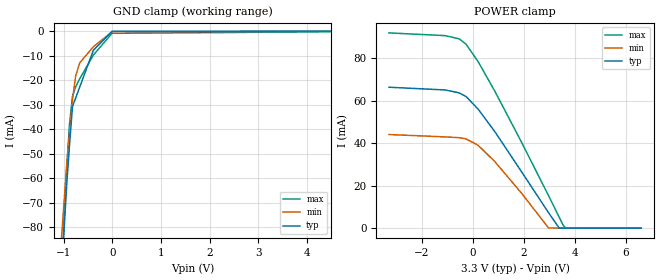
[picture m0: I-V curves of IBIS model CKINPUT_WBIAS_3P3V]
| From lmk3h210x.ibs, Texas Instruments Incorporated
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[Model]   CKINPUT_WBIAS_3P3V
Model_type   Input
Vinl = 0.2
Vinh = 0.4
|   typ   min   max
C_comp   1.5pF   1.4pF   1.6pF
[Voltage Range]   3.3   2.97   3.597
[Temperature Range]   50   125   -40
[Power Clamp Reference]   3.3   2.97   3.597
[GND Clamp Reference]   0   0   0
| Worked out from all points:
|   GND clamp passes 1 mA (typ) near -0.05 V on its own axis
[GND Clamp]
|   Voltage   I(typ)   I(min)   I(max)
-3.3V     -1.023A    -928mA     -1.13A
-1.209V   -162mA     -139.3mA   -169mA
-1.065V   -107.8mA   -91.57mA   -107.2mA
-1.051V   -102.5mA   -86.96mA   -101.7mA
-934.8mV  -62.44mA   -54.38mA   -56.05mA
-877.3mV  -46.53mA   -41.62mA   -37.87mA
-816.2mV  -30.81mA   -28.06mA   -26.49mA
-751.2mV  -27.32mA   -18.29mA   -22.73mA
-668.2mV  -22.87mA   -12.99mA   -19.46mA
-388.1mV  -7.841mA   -6.381mA   -9.788mA
-3.764mV  -73.56uA   -283.4uA   -906.7uA
6.6V      0A         0A         0A
[POWER Clamp]
|   Voltage   I(typ)   I(min)   I(max)
-3.3V     66.27mA    44.03mA    91.82mA
-1.091V   64.99mA    42.91mA    90.53mA
-541.9mV  63.61mA    42.54mA    89.01mA
-271.8mV  61.9mA     41.99mA    86.51mA
207.3mV   55.89mA    38.9mA     78.19mA
858.4mV   45.36mA    31.27mA    64.37mA
1.912V    26.42mA    16.34mA    40.26mA
2.964V    7.29mA     100.4uA    15.3mA
3.386V    0A         0A         5.1mA
3.55V     0A         0A         1.152mA
3.653V    0A         0A         0A
6.6V      0A         0A         0A
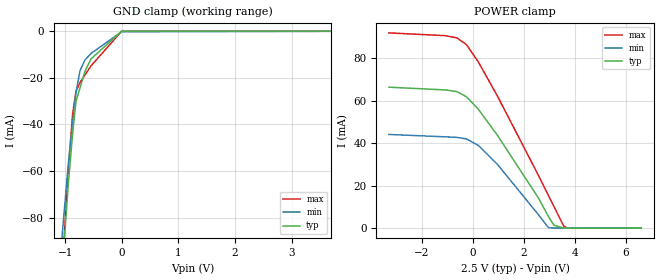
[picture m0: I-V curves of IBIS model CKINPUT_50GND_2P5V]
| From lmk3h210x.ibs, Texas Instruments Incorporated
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[Model]   CKINPUT_50GND_2P5V
Model_type   Input
Vinl = 0.2
Vinh = 0.4
|   typ   min   max
C_comp   1.5pF   1.4pF   1.6pF
[Voltage Range]   2.5   2.25   2.75
[Temperature Range]   50   125   -40
[Power Clamp Reference]   2.5   2.25   2.75
[GND Clamp Reference]   0   0   0
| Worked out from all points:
|   GND clamp passes 1 mA (typ) near -0.05 V on its own axis
[GND Clamp]
|   Voltage   I(typ)   I(min)   I(max)
-3.3V     -1.023A    -928mA     -1.13A
-1.151V   -140.2mA   -118.9mA   -144.2mA
-1.074V   -110.9mA   -94.04mA   -110.7mA
-1.051V   -102.5mA   -86.96mA   -101.9mA
-944.7mV  -65.64mA   -57.1mA    -59.44mA
-868.9mV  -44.36mA   -39.76mA   -35.72mA
-808.8mV  -30.19mA   -26.54mA   -25.79mA
-738.2mV  -24.45mA   -17.01mA   -22.12mA
-649.7mV  -17.24mA   -12.37mA   -18.78mA
-541.2mV  -11.89mA   -9.581mA   -14.87mA
-3.764mV  -73.56uA   -283.4uA   -91.89uA
6.6V      0A         0A         0A
[POWER Clamp]
-3.3V     66.27mA    44.03mA    91.82mA
-1.074V   64.97mA    42.9mA     90.51mA
-636.3mV  64.21mA    42.66mA    89.48mA
-258.6mV  61.78mA    41.95mA    86.34mA
207.3mV   55.92mA    38.9mA     78.18mA
957.4mV   43.66mA    29.96mA    62.14mA
2.566V    14.15mA    6.307mA    24.82mA
2.964V    5.373mA    100.4uA    15.27mA
3.174V    1.35mA     0A         10.21mA
3.561V    -19.07uA   0A         884.6uA
3.708V    -68.5uA    0A         0A
6.6V      0A         0A         0A
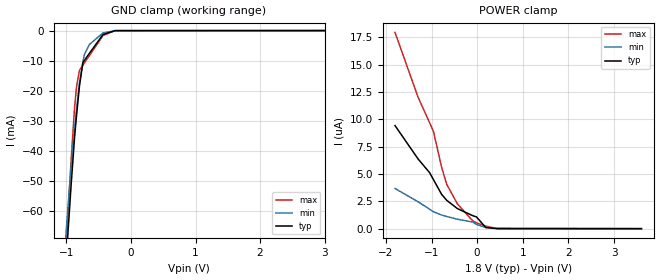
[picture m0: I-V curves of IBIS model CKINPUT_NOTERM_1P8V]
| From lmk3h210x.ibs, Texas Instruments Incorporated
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[Model]   CKINPUT_NOTERM_1P8V
Model_type   Input
Vinl = 0.2
Vinh = 0.4
|   typ   min   max
C_comp   1.5pF   1.4pF   1.6pF
[Voltage Range]   1.8   1.71   1.89
[Temperature Range]   50   125   -40
[Power Clamp Reference]   1.8   1.71   1.89
[GND Clamp Reference]   0   0   0
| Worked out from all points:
|   GND clamp passes 1 mA (typ) near -0.41 V on its own axis
[GND Clamp]
|   Voltage   I(typ)   I(min)   I(max)
-1.8V     -389.6mA   -347.8mA   -423.4mA
-1.005V   -76.24mA   -66.85mA   -71.29mA
-926.6mV  -51.02mA   -44.76mA   -42.66mA
-873.8mV  -35.39mA   -32.34mA   -25.47mA
-841.9mV  -27.83mA   -25.8mA    -18.39mA
-797.7mV  -18.31mA   -17.26mA   -13.14mA
-744.9mV  -10.64mA   -10.39mA   -11.48mA
-720.6mV  -9.896mA   -7.908mA   -10.71mA
-643.7mV  -7.534mA   -4.603mA   -8.278mA
-433.6mV  -1.316mA   -796.2uA   -1.64mA
-246.2mV  -24.72uA   -20.8uA    -13.5uA
3.6V      0A         0A         0A
[POWER Clamp]
|   Voltage   I(typ)   I(min)   I(max)
-1.8V     9.428uA    3.675uA    17.95uA
-1.295V   6.381uA    2.46uA     12.03uA
-1.04V    5.109uA    1.775uA    9.674uA
-957.7mV  4.488uA    1.548uA    8.894uA
-777.2mV  3.128uA    1.244uA    5.598uA
-666.5mV  2.591uA    1.111uA    4.053uA
-432.7mV  1.834uA    861.5nA    2.263uA
-96.2mV   1.188uA    605nA      706nA
-13.98mV  1.073uA    384.4nA    528.4nA
187.6mV   105.9nA    109.1nA    233.9nA
443.4mV   0A         32.14nA    0A
3.6V      0A         0A         0A
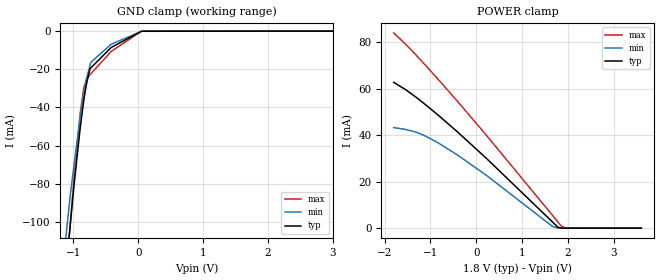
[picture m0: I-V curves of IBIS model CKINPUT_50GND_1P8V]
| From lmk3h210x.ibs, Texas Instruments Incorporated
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[Model]   CKINPUT_50GND_1P8V
Model_type   Input
Vinl = 0.2
Vinh = 0.4
|   typ   min   max
C_comp   1.5pF   1.4pF   1.6pF
[Voltage Range]   1.8   1.71   1.89
[Temperature Range]   50   125   -40
[Power Clamp Reference]   1.8   1.71   1.89
[GND Clamp Reference]   0   0   0
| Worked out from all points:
|   GND clamp passes 1 mA (typ) near -0.05 V on its own axis
[GND Clamp]
|   Voltage   I(typ)   I(min)   I(max)
-1.8V     -399.1mA   -354.1mA   -436.1mA
-1.137V   -133.8mA   -114.7mA   -137.8mA
-1.05V    -101.9mA   -86.43mA   -101.5mA
-988.7mV  -80.14mA   -69.6mA    -76.04mA
-894.5mV  -50.39mA   -44.5mA    -42.71mA
-839.7mV  -36.15mA   -32.93mA   -29.62mA
-799.7mV  -27.85mA   -24.95mA   -25.26mA
-743.5mV  -19.7mA    -17.99mA   -22.83mA
-729.7mV  -19.23mA   -16.29mA   -22.32mA
-418.2mV  -8.588mA   -6.921mA   -10.69mA
50.38mV   -92.85uA   -74.37uA   0A
3.6V      0A         0A         0A
[POWER Clamp]
|   Voltage   I(typ)   I(min)   I(max)
-1.8V     62.67mA    43.23mA    83.91mA
-1.539V   59.51mA    42.41mA    79.02mA
-1.318V   56.36mA    41.32mA    74.52mA
-1.111V   53.13mA    39.63mA    70.1mA
-835.3mV  48.67mA    36.72mA    64.09mA
-418.2mV  41.53mA    31.56mA    54.72mA
231.4mV   29.81mA    22.56mA    39.68mA
1.664V    2.633mA    722uA      5.471mA
1.777V    444.1uA    0A         2.738mA
1.858V    0A         0A         770uA
1.958V    0A         0A         0A
3.6V      0A         0A         0A
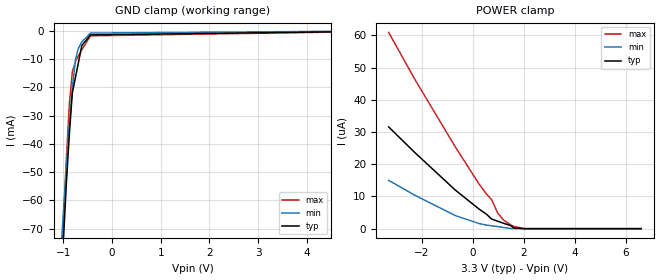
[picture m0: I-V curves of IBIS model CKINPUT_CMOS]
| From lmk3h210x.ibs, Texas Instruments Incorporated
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[Model]   CKINPUT_CMOS
Model_type   Input
Vinl = 0.5
Vinh = 1.2
|   typ   min   max
C_comp   1.5pF   1.4pF   1.6pF
[Voltage Range]   3.3   2.97   3.597
[Temperature Range]   50   125   -40
[Power Clamp Reference]   3.3   2.97   3.597
[GND Clamp Reference]   0   0   0
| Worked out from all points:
|   GND clamp passes 1 mA (typ) near -0.41 V on its own axis
[GND Clamp]
|   Voltage   I(typ)   I(min)   I(max)
-3.3V     -1.015A    -923.7mA   -1.116A
-1.08V    -103.9mA   -88.87mA   -101.9mA
-1.05V    -92.77mA   -79.14mA   -89.89mA
-1.021V   -82.14mA   -70.55mA   -78.34mA
-937.6mV  -54.32mA   -47.76mA   -45.53mA
-874.8mV  -36.37mA   -33.4mA    -25.73mA
-813.6mV  -21.97mA   -19.98mA   -14.47mA
-749.1mV  -16.43mA   -10.38mA   -10.86mA
-697mV    -11.95mA   -6.522mA   -9.166mA
-619.3mV  -5.276mA   -3.993mA   -6.738mA
-441mV    -1.521mA   -879.1uA   -1.855mA
6.6V      0A         0A         0A
[POWER Clamp]
|   Voltage   I(typ)   I(min)   I(max)
-3.3V     31.59uA    15uA       60.94uA
-2.284V   23.71uA    10.43uA    46.51uA
-697mV    12.05uA    4.095uA    25.51uA
248.9mV   6.057uA    1.574uA    13.82uA
540.5mV   4.458uA    1.101uA    10.73uA
737.3mV   2.976uA    894nA      8.989uA
979.7mV   2.301uA    639.5nA    4.797uA
1.214V    1.648uA    347.3nA    2.6uA
1.496V    924.3nA    80.75nA    1.143uA
1.614V    177.9nA    48.28nA    697.8nA
2.025V    0A         0A         1.319nA
6.6V      0A         0A         0A
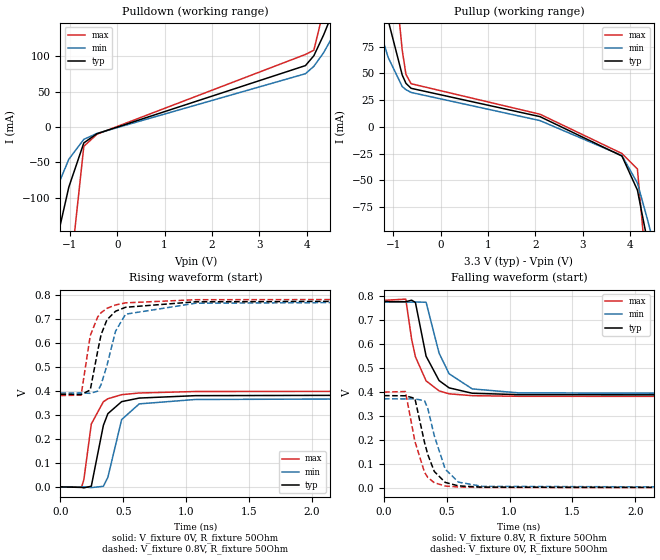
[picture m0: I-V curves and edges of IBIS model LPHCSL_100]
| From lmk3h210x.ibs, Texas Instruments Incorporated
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[Model]   LPHCSL_100
Model_type   Output
Polarity   Non-Inverting
Vmeas = 0.375
Vref = 0
Cref = 2pF
Rref = 100000
|   typ   min   max
C_comp   2.5pF   2pF   3pF
[Voltage Range]   3.3   3.135   3.465
[Temperature Range]   45   125   -40
[Pullup Reference]   3.3   3.135   3.465
[Pulldown Reference]   -0   0   -0
[Power Clamp Reference]   3.3   3.135   3.465
[GND Clamp Reference]   0   0   0
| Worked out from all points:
|   slope of the pulldown table from 0 to 0.495 V, typ, clamps not added: 46.9 ohm
|   slope of the pullup table from 0 to 0.495 V, typ, clamps not added: 121 ohm
|   falling waveform, V_fixture 0.8V, R_fixture 50Ohm: 20-80 % time 134ps typ, 152ps min, 118ps max; typ from 0.778 V to 0.387 V
|   rising waveform, V_fixture 0V, R_fixture 50Ohm: 20-80 % time 98ps typ, 113ps min, 87.4ps max; typ from 0 V to 0.385 V
|   rising waveform, V_fixture 0.8V, R_fixture 50Ohm: 20-80 % time 109ps typ, 133ps min, 96ps max; typ from 0.387 V to 0.778 V
|   falling waveform, V_fixture 0V, R_fixture 50Ohm: 20-80 % time 119ps typ, 126ps min, 110ps max; typ from 0.385 V to 0 V
[Pulldown]
|   Voltage   I(typ)   I(min)   I(max)
-3.3V     -899.1mA   -528.2mA   -2.692A
-1.944V   -395.2mA   -213.5mA   -1.201A
-1.241V   -149.6mA   -80.86mA   -439.1mA
-1.023V   -85.09mA   -45.71mA   -224.9mA
-706.2mV  -22.59mA   -17.56mA   -27.46mA
-429mV    -9.629mA   -9.193mA   -10.32mA
3.977V    86.76mA    75.29mA    102.5mA
4.155V    100.7mA    85.73mA    108.6mA
4.363V    130.4mA    105.2mA    165.8mA
4.59V     167.8mA    132.6mA    261.3mA
4.907V    230.9mA    176.3mA    408.7mA
6.6V      624.2mA    482.1mA    1.302A
[Pullup]
|   Voltage   I(typ)   I(min)   I(max)
-3.3V     597.5mA    427.6mA    1.347A
-1.617V   206.2mA    137.9mA    457.2mA
-1.112V   99.56mA    64.93mA    204.4mA
-815.1mV  48.52mA    37.71mA    71.73mA
-735.9mV  40.7mA     34.8mA     49.01mA
-627mV    36.08mA    32.22mA    40.36mA
2.095V    9.633mA    5.938mA    11.89mA
3.828V    -27.21mA   -26.75mA   -24.82mA
4.155V    -59.05mA   -52.46mA   -39.3mA
4.372V    -108mA     -87.23mA   -147.2mA
4.491V    -142.5mA   -107.7mA   -240.8mA
6.6V      -930.7mA   -594.1mA   -2.541A
[Ramp]
R_load = 50
|   typ   min   max
dV/dt_r   0.230932/9.7996e-11   0.222863/1.12745e-10   0.239773/8.73447e-11
dV/dt_f   0.234814/1.33534e-10   0.230538/1.51007e-10   0.241163/1.17227e-10
[Falling Waveform]
V_fixture = 0.8V
V_fixture_min = 0.8V
V_fixture_max = 0.8V
R_fixture = 50Ohm
C_fixture = 0F
|   Time   V(typ)   V(min)   V(max)
0s        777.9mV    775.9mV    783.1mV
173.3ps   777.2mV    775.5mV    788mV
220.1ps   783.6mV    775.4mV    620.1mV
250.2ps   773.8mV    776.2mV    547.1mV
335.1ps   549.9mV    774.8mV    446.8mV
438.6ps   448mV      562.4mV    405mV
518.4ps   417.6mV    476.5mV    392.7mV
702.4ps   395.1mV    413.2mV    384.9mV
1.074ns   389.2mV    396.6mV    382.4mV
5ns       386.6mV    391.7mV    381.2mV
[Rising Waveform]
V_fixture = 0V
V_fixture_min = 0V
V_fixture_max = 0V
R_fixture = 50Ohm
C_fixture = 0F
|   Time   V(typ)   V(min)   V(max)
0s        187uV      283.4uV    113.6uV
167.8ps   -1.962mV   152.4uV    -1.11mV
186.3ps   -3.82mV    138uV      30.16mV
245.8ps   3.068mV    -2.748mV   262.6mV
341.6ps   256.3mV    2.698mV    355.1mV
377.6ps   305.6mV    40.1mV     367.7mV
487.3ps   355.7mV    280.9mV    384.7mV
627.4ps   370.6mV    346.4mV    391.7mV
1.074ns   380.6mV    364.6mV    397.9mV
5ns       385.1mV    371.7mV    399.7mV
[Rising Waveform]
V_fixture = 0.8V
V_fixture_min = 0.8V
V_fixture_max = 0.8V
R_fixture = 50Ohm
C_fixture = 0F
|   Time   V(typ)   V(min)   V(max)
0s        386.6mV    391.7mV    381.2mV
164.7ps   385.2mV    391.9mV    382.7mV
237.3ps   404.2mV    390.3mV    631.1mV
296.4ps   565.9mV    399.4mV    708.7mV
323.7ps   635.2mV    426.7mV    726.5mV
370.6ps   697.3mV    507.6mV    744.7mV
438.6ps   732.6mV    649.3mV    758.7mV
518.4ps   749.1mV    720.2mV    767.6mV
1.074ns   771.9mV    765.9mV    780.6mV
5ns       777.9mV    775.8mV    783.1mV
[Falling Waveform]
|Gnd
V_fixture = 0V
V_fixture_min = 0V
V_fixture_max = 0V
R_fixture = 50Ohm
C_fixture = 0F
|   Time   V(typ)   V(min)   V(max)
0s        385.1mV    371.8mV    399.8mV
170.6ps   384.5mV    371.5mV    402.3mV
245.8ps   373.7mV    371.8mV    194.7mV
322.9ps   189mV      363.7mV    64.61mV
349.3ps   138.1mV    330.6mV    43.25mV
400.4ps   68.64mV    217.6mV    21.6mV
487.3ps   22.89mV    78.43mV    7.784mV
592ps     8.424mV    24.03mV    3.782mV
783.6ps   3.06mV     6.308mV    1.849mV
5ns       186.4uV    283.2uV    112.6uV
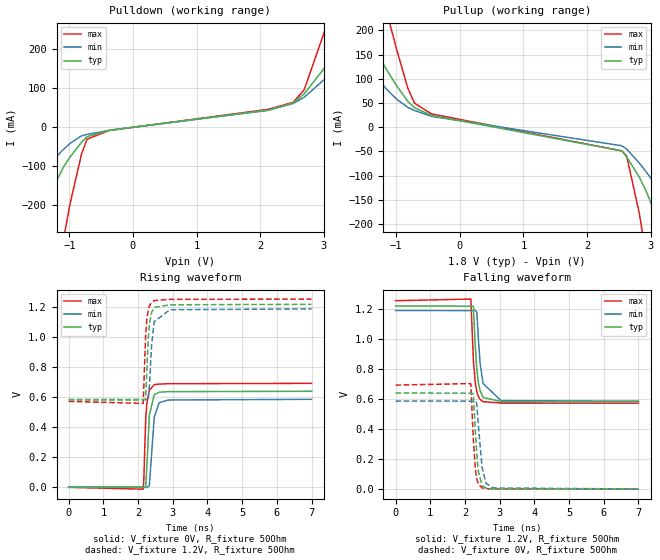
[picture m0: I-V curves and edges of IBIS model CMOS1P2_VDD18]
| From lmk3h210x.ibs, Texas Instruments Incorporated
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[Model]   CMOS1P2_VDD18
Model_type   Output
Polarity   Non-Inverting
Vmeas = 0.9
Vref = 0.9
Cref = 2pF
Rref = 100000
|   typ   min   max
C_comp   2.5pF   2pF   3pF
[Voltage Range]   1.8   1.71   1.89
[Temperature Range]   45   125   -40
[Pullup Reference]   1.8   1.71   1.89
[Pulldown Reference]   0   -0   -0
[Power Clamp Reference]   1.8   1.71   1.89
[GND Clamp Reference]   0   0   0
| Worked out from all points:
|   slope of the pulldown table from 0 to 0.27 V, typ, clamps not added: 46.7 ohm
|   slope of the pullup table from 0 to 0.27 V, typ, clamps not added: 45.5 ohm
|   falling waveform, V_fixture 1.2V, R_fixture 50Ohm: 20-80 % time 115ps typ, 147ps min, 100ps max; typ from 1.22 V to 0.581 V
|   rising waveform, V_fixture 0V, R_fixture 50Ohm: 20-80 % time 87.9ps typ, 107ps min, 76.4ps max; typ from 0 V to 0.639 V
|   rising waveform, V_fixture 1.2V, R_fixture 50Ohm: 20-80 % time 85.2ps typ, 105ps min, 77.4ps max; typ from 0.581 V to 1.22 V
|   falling waveform, V_fixture 0V, R_fixture 50Ohm: 20-80 % time 108ps typ, 138ps min, 98.5ps max; typ from 0.639 V to 0 V
[Pulldown]
|   Voltage   I(typ)   I(min)   I(max)
-1.8V     -348.1mA   -190.5mA   -1.047A
-1.411V   -207.4mA   -111.6mA   -626.1mA
-1.093V   -103.4mA   -57.49mA   -291.6mA
-990mV    -77.57mA   -42.23mA   -199mA
-806.4mV  -38.77mA   -22.26mA   -68.97mA
-720mV    -24.68mA   -18.72mA   -31.09mA
-369mV    -8.092mA   -8.074mA   -8.438mA
2.126V    43.84mA    43.24mA    45.83mA
2.52V     62.07mA    60.84mA    63.89mA
2.693V    85.76mA    77.08mA    96.32mA
3.109V    172.6mA    137mA      291.8mA
3.6V      287mA      218.8mA    549.2mA
[Pullup]
|   Voltage   I(typ)   I(min)   I(max)
-1.8V     265.9mA    179.6mA    578.2mA
-1.152V   119.2mA    78.6mA     240.4mA
-990mV    85.03mA    57.39mA    159.7mA
-817.2mV  53.27mA    40.88mA    80.81mA
-709.2mV  40.09mA    34.26mA    49.33mA
-444.6mV  24.23mA    22.25mA    27.37mA
2.547V    -48.97mA   -38.41mA   -49.02mA
2.623V    -61.46mA   -45.25mA   -59.45mA
2.822V    -103mA     -74.18mA   -177.9mA
2.93V     -132.1mA   -92.28mA   -265.7mA
3.13V     -197.9mA   -128.1mA   -463.8mA
3.6V      -370.6mA   -226.7mA   -978.4mA
[Ramp]
R_load = 50
|   typ   min   max
dV/dt_r   0.383123/8.79707e-11   0.350417/1.07146e-10   0.414781/7.6285e-11
dV/dt_f   0.381702/1.14879e-10   0.361584/1.46587e-10   0.408396/1.00091e-10
[Falling Waveform]
V_fixture = 1.2V
V_fixture_min = 1.2V
V_fixture_max = 1.2V
R_fixture = 50Ohm
C_fixture = 0F
|   Time   V(typ)   V(min)   V(max)
0s        1.217V     1.187V     1.252V
2.17ns    1.216V     1.186V     1.263V
2.243ns   1.216V     1.186V     856.5mV
2.295ns   960.4mV    1.19V      711.7mV
2.341ns   796.5mV    1.176V     649mV
2.382ns   713.6mV    1.018V     618.3mV
2.436ns   655.1mV    837.6mV    596.7mV
2.52ns    610.1mV    702.7mV    581.3mV
3.04ns    582mV      588.3mV    572.2mV
7ns       580.9mV    584.1mV    571.4mV
[Rising Waveform]
V_fixture = 0V
V_fixture_min = 0V
V_fixture_max = 0V
R_fixture = 50Ohm
C_fixture = 0F
|   Time   V(typ)   V(min)   V(max)
0s        303uV      1.493mV    224.7uV
2.147ns   351.5uV    1.434mV    -12.05mV
2.163ns   -1.108mV   1.434mV    36.21mV
2.22ns    -487.3uV   535.5uV    456.3mV
2.252ns   137.3mV    -2.299mV   556.2mV
2.325ns   481mV      11.27mV    645.6mV
2.465ns   616.1mV    467.2mV    683.1mV
2.608ns   632.5mV    563mV      686.3mV
2.865ns   636.4mV    580.8mV    689.4mV
7ns       638.8mV    585.5mV    691.5mV
[Rising Waveform]
V_fixture = 1.2V
V_fixture_min = 1.2V
V_fixture_max = 1.2V
R_fixture = 50Ohm
C_fixture = 0F
|   Time   V(typ)   V(min)   V(max)
0s        581.1mV    584.4mV    571.5mV
2.147ns   581.2mV    584.4mV    558.2mV
2.216ns   584mV      583.8mV    1.003V
2.252ns   775.6mV    581.3mV    1.117V
2.289ns   976.9mV    584.6mV    1.175V
2.33ns    1.094V     687.7mV    1.208V
2.392ns   1.165V     952.8mV    1.23V
2.465ns   1.196V     1.102V     1.242V
2.915ns   1.214V     1.181V     1.25V
7ns       1.217V     1.187V     1.252V
[Falling Waveform]
|Gnd
V_fixture = 0V
V_fixture_min = 0V
V_fixture_max = 0V
R_fixture = 50Ohm
C_fixture = 0F
|   Time   V(typ)   V(min)   V(max)
0s        638.9mV    585.5mV    691.5mV
2.168ns   637.5mV    585mV      701.5mV
2.24ns    634.8mV    585mV      335.6mV
2.302ns   373.7mV    587.4mV    131mV
2.339ns   240.9mV    570.7mV    71.45mV
2.382ns   124.3mV    434.3mV    35.43mV
2.492ns   24.35mV    146.2mV    8.669mV
2.608ns   6.864mV    38.74mV    3.605mV
2.82ns    2.352mV    8.059mV    1.782mV
7ns       133.5uV    1.493mV    89.28uV
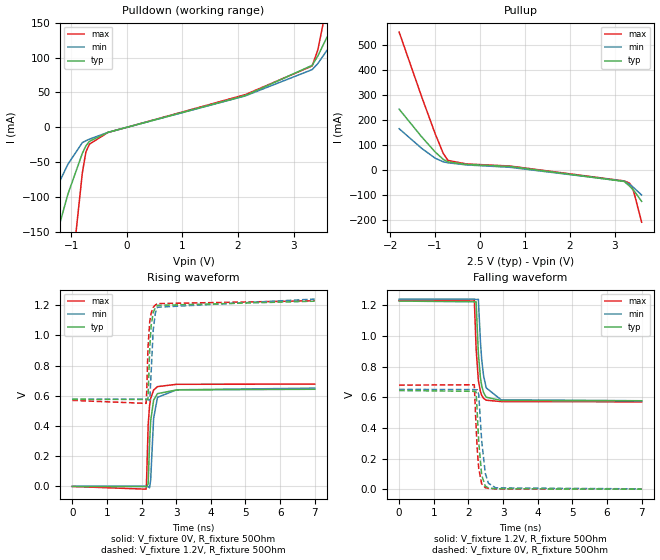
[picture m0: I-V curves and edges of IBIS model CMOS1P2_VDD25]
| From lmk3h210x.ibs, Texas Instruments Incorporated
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[Model]   CMOS1P2_VDD25
Model_type   Output
Polarity   Non-Inverting
Vmeas = 1.25
Vref = 1.25
Cref = 2pF
Rref = 100000
|   typ   min   max
C_comp   2.5pF   2pF   3pF
[Voltage Range]   2.5   2.375   2.625
[Temperature Range]   45   125   -40
[Pullup Reference]   2.5   2.375   2.625
[Pulldown Reference]   -0   0   -0
[Power Clamp Reference]   2.5   2.375   2.625
[GND Clamp Reference]   0   0   0
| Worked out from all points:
|   slope of the pulldown table from 0 to 0.375 V, typ, clamps not added: 46.2 ohm
|   slope of the pullup table from 0 to 0.375 V, typ, clamps not added: 136 ohm
|   falling waveform, V_fixture 1.2V, R_fixture 50Ohm: 20-80 % time 114ps typ, 144ps min, 99.4ps max; typ from 1.23 V to 0.577 V
|   rising waveform, V_fixture 0V, R_fixture 50Ohm: 20-80 % time 88.9ps typ, 104ps min, 80.6ps max; typ from 0 V to 0.644 V
|   rising waveform, V_fixture 1.2V, R_fixture 50Ohm: 20-80 % time 85.7ps typ, 98.4ps min, 82.4ps max; typ from 0.577 V to 1.23 V
|   falling waveform, V_fixture 0V, R_fixture 50Ohm: 20-80 % time 110ps typ, 142ps min, 98.7ps max; typ from 0.644 V to 0 V
[Pulldown]
|   Voltage   I(typ)   I(min)   I(max)
-1.8V     -348.8mA   -191.4mA   -1.047A
-1.433V   -216.2mA   -116.8mA   -649.9mA
-1.255V   -152.5mA   -85.79mA   -456.3mA
-1.06V    -96.13mA   -53.23mA   -260.5mA
-801mV    -37.77mA   -22.19mA   -65.78mA
-736.2mV  -26.89mA   -19.54mA   -35.44mA
-671.4mV  -20.32mA   -17.16mA   -24.33mA
-342mV    -7.521mA   -7.597mA   -7.727mA
2.131V    45.25mA    44.86mA    46.7mA
3.335V    88.79mA    82.62mA    87.86mA
3.438V    102.3mA    91.42mA    111.1mA
3.6V      129mA      110.2mA    175.5mA
[Pullup]
|   Voltage   I(typ)   I(min)   I(max)
-1.8V     242.9mA    164.6mA    551.7mA
-1.298V   132mA      85.96mA    292.3mA
-995.4mV  71mA       46.23mA    143.4mA
-817.2mV  41.76mA    32.11mA    65.46mA
-714.6mV  31.84mA    28.25mA    37.78mA
-304.2mV  21.4mA     19.67mA    23.48mA
662.4mV   13.45mA    10.1mA     15.3mA
3.211V    -46.59mA   -45.59mA   -44.49mA
3.33V     -64.85mA   -58.05mA   -53.11mA
3.379V    -74.17mA   -64.92mA   -65.98mA
3.433V    -84.6mA    -73.15mA   -93.39mA
3.6V      -126.3mA   -101mA     -209.8mA
[Ramp]
R_load = 50
|   typ   min   max
dV/dt_r   0.386258/8.84838e-11   0.389575/1.03396e-10   0.406744/8.06125e-11
dV/dt_f   0.390552/1.13765e-10   0.398493/1.44317e-10   0.396636/9.94653e-11
[Falling Waveform]
V_fixture = 1.2V
V_fixture_min = 1.2V
V_fixture_max = 1.2V
R_fixture = 50Ohm
C_fixture = 0F
|   Time   V(typ)   V(min)   V(max)
0s        1.228V     1.241V     1.231V
2.17ns    1.223V     1.241V     1.235V
2.222ns   1.223V     1.238V     917.2mV
2.287ns   885.3mV    1.239V     709.8mV
2.347ns   726.3mV    961.6mV    636.5mV
2.383ns   675.5mV    847.3mV    612.5mV
2.438ns   629.7mV    738.9mV    593mV
2.515ns   600.2mV    660.8mV    580.6mV
2.945ns   579mV      582.9mV    571.9mV
7ns       576.9mV    577.2mV    570.1mV
[Rising Waveform]
V_fixture = 0V
V_fixture_min = 0V
V_fixture_max = 0V
R_fixture = 50Ohm
C_fixture = 0F
|   Time   V(typ)   V(min)   V(max)
0s        706.9nV    1.793mV    181.9uV
2.131ns   -94.94uV   1.682mV    -17.66mV
2.143ns   -3.785mV   1.681mV    23.62mV
2.191ns   16.36mV    -1.624mV   405.7mV
2.231ns   286.6mV    -8.637mV   534.2mV
2.263ns   432.1mV    42.6mV     583.2mV
2.348ns   571.4mV    450.4mV    638.3mV
2.46ns    615.1mV    590.2mV    661.3mV
3.013ns   639.3mV    640.3mV    676.7mV
7ns       643.8mV    651.1mV    678.1mV
[Rising Waveform]
V_fixture = 1.2V
V_fixture_min = 1.2V
V_fixture_max = 1.2V
R_fixture = 50Ohm
C_fixture = 0F
|   Time   V(typ)   V(min)   V(max)
0s        577.1mV    577.5mV    570.2mV
2.132ns   576.9mV    577.3mV    550.4mV
2.144ns   572.6mV    577.3mV    596.9mV
2.186ns   582mV      574.4mV    919.8mV
2.237ns   914.9mV    571.5mV    1.094V
2.278ns   1.067V     760.5mV    1.149V
2.336ns   1.151V     1.035V     1.186V
2.399ns   1.186V     1.148V     1.202V
2.46ns    1.199V     1.187V     1.211V
7ns       1.227V     1.241V     1.23V
[Falling Waveform]
|Gnd
V_fixture = 0V
V_fixture_min = 0V
V_fixture_max = 0V
R_fixture = 50Ohm
C_fixture = 0F
|   Time   V(typ)   V(min)   V(max)
0s        643.8mV    651.1mV    679.2mV
2.169ns   638.9mV    650.2mV    681.4mV
2.222ns   634.4mV    647.6mV    403.3mV
2.257ns   485.9mV    648.7mV    250.6mV
2.298ns   308.2mV    617.3mV    134.2mV
2.382ns   90.99mV    317.7mV    35.06mV
2.487ns   20.2mV     103.4mV    9.613mV
2.579ns   7.779mV    38.12mV    4.869mV
2.79ns    2.601mV    8.461mV    2.149mV
7ns       706.9nV    1.793mV    60.83uV
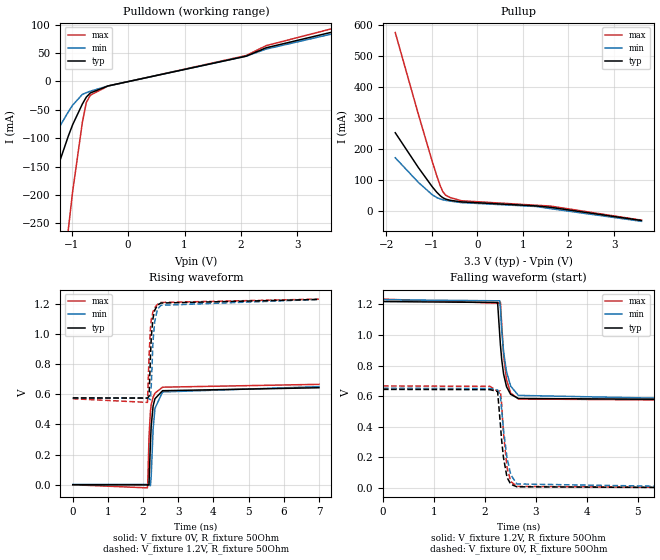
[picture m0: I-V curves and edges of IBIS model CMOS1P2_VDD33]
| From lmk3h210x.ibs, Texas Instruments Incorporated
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[Model]   CMOS1P2_VDD33
Model_type   Output
Polarity   Non-Inverting
Vmeas = 1.65
Vref = 1.65
Cref = 2pF
Rref = 100000
|   typ   min   max
C_comp   2.5pF   2pF   3pF
[Voltage Range]   3.3   3.135   3.465
[Temperature Range]   45   125   -40
[Pullup Reference]   3.3   3.135   3.465
[Pulldown Reference]   0   0   0
[Power Clamp Reference]   3.3   3.135   3.465
[GND Clamp Reference]   0   0   0
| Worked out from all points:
|   slope of the pulldown table from 0 to 0.495 V, typ, clamps not added: 46.2 ohm
|   slope of the pullup table from 0 to 0.495 V, typ, clamps not added: 136 ohm
|   falling waveform, V_fixture 1.2V, R_fixture 50Ohm: 20-80 % time 114ps typ, 144ps min, 101ps max; typ from 1.22 V to 0.576 V
|   rising waveform, V_fixture 0V, R_fixture 50Ohm: 20-80 % time 91.2ps typ, 104ps min, 86.4ps max; typ from 0 V to 0.644 V
|   rising waveform, V_fixture 1.2V, R_fixture 50Ohm: 20-80 % time 88.4ps typ, 101ps min, 87.6ps max; typ from 0.576 V to 1.23 V
|   falling waveform, V_fixture 0V, R_fixture 50Ohm: 20-80 % time 111ps typ, 144ps min, 102ps max; typ from 0.644 V to 0 V
[Pulldown]
|   Voltage   I(typ)   I(min)   I(max)
-1.8V     -348.9mA   -191.8mA   -1.047A
-1.53V    -250.6mA   -135.9mA   -752.1mA
-1.26V    -154.5mA   -87.28mA   -461.9mA
-1.06V    -96.18mA   -53.52mA   -260.5mA
-984.6mV  -76.48mA   -41.87mA   -194.7mA
-811.8mV  -39.85mA   -22.85mA   -72.3mA
-741.6mV  -27.67mA   -19.81mA   -37.16mA
-671.4mV  -20.35mA   -17.23mA   -24.3mA
-358.2mV  -7.921mA   -8.01mA    -8.142mA
2.093V    44.58mA    44.58mA    45.68mA
2.444V    59.28mA    57.05mA    63.06mA
3.6V      86.62mA    83.46mA    92.7mA
[Pullup]
|   Voltage   I(typ)   I(min)   I(max)
-1.8V     251.1mA    170.3mA    574.6mA
-1.292V   138.4mA    90.67mA    310.1mA
-984.6mV  75.85mA    50.4mA     156.4mA
-887.4mV  58.63mA    41.75mA    111.1mA
-811.8mV  47.5mA     37.07mA    79.37mA
-757.8mV  41.46mA    34.83mA    61.29mA
-698.4mV  37mA       32.99mA    49.81mA
-601.2mV  33.2mA     30.56mA    42.15mA
-347.4mV  27.85mA    25.53mA    31.51mA
1.289V    14.83mA    13mA       16.97mA
1.597V    10.48mA    6.216mA    14.49mA
3.6V      -32.2mA    -34.83mA   -31.24mA
[Ramp]
R_load = 50
|   typ   min   max
dV/dt_r   0.386286/9.09103e-11   0.389583/1.03881e-10   0.39977/8.64971e-11
dV/dt_f   0.385016/1.14307e-10   0.392566/1.44385e-10   0.397993/1.00966e-10
[Falling Waveform]
V_fixture = 1.2V
V_fixture_min = 1.2V
V_fixture_max = 1.2V
R_fixture = 50Ohm
C_fixture = 0F
|   Time   V(typ)   V(min)   V(max)
0s        1.218V     1.23V      1.234V
2.249ns   1.212V     1.223V     1.208V
2.29ns    1.005V     1.223V     1.209V
2.304ns   937.1mV    1.175V     1.214V
2.33ns    838mV      1.028V     1.067V
2.367ns   743.4mV    889.1mV    866.2mV
2.424ns   661.5mV    759.1mV    707mV
2.504ns   611.9mV    665.8mV    620.8mV
2.656ns   584.5mV    604.6mV    581.4mV
7ns       576.3mV    575.3mV    570.7mV
[Rising Waveform]
V_fixture = 0V
V_fixture_min = 0V
V_fixture_max = 0V
R_fixture = 50Ohm
C_fixture = 0F
|   Time   V(typ)   V(min)   V(max)
0s        707.9nV    1.787mV    4.233uV
2.123ns   -974.5uV   1.632mV    -20.8mV
2.133ns   -3.179mV   1.631mV    16.04mV
2.168ns   613.1uV    -2.58mV    314mV
2.208ns   274.1mV    -6.712mV   485.1mV
2.23ns    387.9mV    55.13mV    530.8mV
2.285ns   523.2mV    369.9mV    581.7mV
2.337ns   570.7mV    507mV      607.7mV
2.553ns   624.1mV    615.9mV    647.5mV
7ns       643.8mV    651.1mV    666.3mV
[Rising Waveform]
V_fixture = 1.2V
V_fixture_min = 1.2V
V_fixture_max = 1.2V
R_fixture = 50Ohm
C_fixture = 0F
|   Time   V(typ)   V(min)   V(max)
0s        576.4mV    575.3mV    570.8mV
2.124ns   575.2mV    575mV      546.5mV
2.171ns   587.8mV    569.1mV    862.7mV
2.208ns   843.8mV    565.1mV    1.035V
2.234ns   983.2mV    667mV      1.096V
2.281ns   1.104V     948.8mV    1.149V
2.328ns   1.157V     1.08V      1.174V
2.405ns   1.191V     1.163V     1.196V
2.504ns   1.206V     1.191V     1.21V
7ns       1.23V      1.23V      1.232V
[Falling Waveform]
|Gnd
V_fixture = 0V
V_fixture_min = 0V
V_fixture_max = 0V
R_fixture = 50Ohm
C_fixture = 0F
|   Time   V(typ)   V(min)   V(max)
0s        643.8mV    651.1mV    666.3mV
2.099ns   642.2mV    649.8mV    663.8mV
2.249ns   629.8mV    640.3mV    630.5mV
2.303ns   417.2mV    604.3mV    633.9mV
2.327ns   316.1mV    515.4mV    553.7mV
2.364ns   198.8mV    383.3mV    356.8mV
2.434ns   68.03mV    195.7mV    132.7mV
2.508ns   23.24mV    85.17mV    41.08mV
2.627ns   6.968mV    25.48mV    9.819mV
7ns       707.9nV    1.787mV    4.233uV
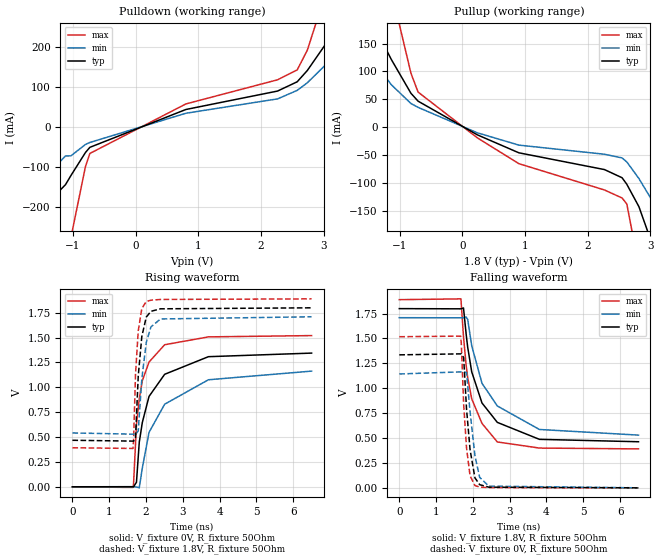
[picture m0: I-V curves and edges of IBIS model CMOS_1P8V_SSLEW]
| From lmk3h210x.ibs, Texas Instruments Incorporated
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[Model]   CMOS_1P8V_SSLEW
Model_type   Output
Polarity   Non-Inverting
Vmeas = 0.9
Vref = 0.9
Cref = 2pF
Rref = 100000
|   typ   min   max
C_comp   2.5pF   2pF   3pF
[Voltage Range]   1.8   1.71   1.89
[Temperature Range]   45   125   -40
[Pullup Reference]   1.8   1.71   1.89
[Pulldown Reference]   0   -0   0
[Power Clamp Reference]   1.8   1.71   1.89
[GND Clamp Reference]   0   0   0
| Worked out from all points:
|   slope of the pulldown table from 0 to 0.27 V, typ, clamps not added: 16.7 ohm
|   slope of the pullup table from 0 to 0.27 V, typ, clamps not added: 17 ohm
|   falling waveform, V_fixture 1.8V, R_fixture 50Ohm: 20-80 % time 657ps typ, 894ps min, 448ps max; typ from 1.8 V to 0.463 V
|   rising waveform, V_fixture 0V, R_fixture 50Ohm: 20-80 % time 573ps typ, 916ps min, 340ps max; typ from 0 V to 1.34 V
|   rising waveform, V_fixture 1.8V, R_fixture 50Ohm: 20-80 % time 151ps typ, 191ps min, 117ps max; typ from 0.468 V to 1.8 V
|   falling waveform, V_fixture 0V, R_fixture 50Ohm: 20-80 % time 179ps typ, 205ps min, 148ps max; typ from 1.33 V to 0 V
[Pulldown]
|   Voltage   I(typ)   I(min)   I(max)
-1.8V     -365.8mA   -207.1mA   -1.065A
-1.249V   -164.3mA   -92.85mA   -468.1mA
-1.12V    -143.7mA   -72.05mA   -359.7mA
-1.033V   -120.9mA   -71.78mA   -275.7mA
-801mV    -63.48mA   -43.35mA   -98.65mA
-730.8mV  -50.55mA   -38.44mA   -65.82mA
802.8mV   43.86mA    34.47mA    57.71mA
2.266V    89.82mA    70.29mA    117.9mA
2.579V    112.9mA    91.44mA    142.5mA
2.741V    141.1mA    110.5mA    191.7mA
3.065V    214mA      160.1mA    349.7mA
3.6V      343.6mA    250.7mA    637.5mA
[Pullup]
|   Voltage   I(typ)   I(min)   I(max)
-1.8V     266.6mA    175.5mA    585.6mA
-1.136V   121.3mA    76.01mA    244.8mA
-822.6mV  60.6mA     42.27mA    96.52mA
-709.2mV  46.52mA    35.37mA    62.81mA
235.8mV   -13.89mA   -10.25mA   -19.26mA
900mV     -46.21mA   -32.39mA   -65.71mA
2.266V    -76.3mA    -48.77mA   -112.9mA
2.547V    -90.95mA   -55.37mA   -127.3mA
2.623V    -102.7mA   -62.57mA   -138mA
2.817V    -143.1mA   -92.52mA   -252.4mA
3.136V    -244.5mA   -152.2mA   -549.1mA
3.6V      -420.8mA   -256.8mA   -1.061A
[Ramp]
R_load = 50
|   typ   min   max
dV/dt_r   0.806001/5.69534e-10   0.697391/9.16036e-10   0.912099/3.39282e-10
dV/dt_f   0.801578/6.52722e-10   0.707271/8.83008e-10   0.898861/4.45576e-10
[Falling Waveform]
V_fixture = 1.8V
V_fixture_min = 1.71V
V_fixture_max = 1.89V
R_fixture = 50Ohm
C_fixture = 0F
|   Time   V(typ)   V(min)   V(max)
0s        1.799V     1.708V     1.889V
1.675ns   1.797V     1.707V     1.897V
1.745ns   1.806V     1.707V     1.517V
1.817ns   1.543V     1.714V     1.231V
1.859ns   1.412V     1.691V     1.107V
1.968ns   1.165V     1.427V     893.7mV
2.247ns   852.2mV    1.05V      647mV
2.664ns   657.2mV    821.8mV    460.8mV
3.808ns   486.9mV    586.1mV    399.4mV
6.5ns     462.8mV    529.4mV    391.1mV
[Rising Waveform]
V_fixture = 0V
V_fixture_min = 0V
V_fixture_max = 0V
R_fixture = 50Ohm
C_fixture = 0F
|   Time   V(typ)   V(min)   V(max)
0s        406uV      722.8uV    167.2uV
1.648ns   1.21mV     1.233mV    -5.957mV
1.662ns   572.3uV    1.238mV    33.11mV
1.741ns   46.52mV    -1.793mV   627.5mV
1.817ns   448.5mV    -10.11mV   884.7mV
1.9ns     647.1mV    189.4mV    1.067V
2.082ns   908.7mV    547mV      1.254V
2.507ns   1.131V     830.6mV    1.428V
3.696ns   1.308V     1.076V     1.507V
6.5ns     1.344V     1.163V     1.52V
[Rising Waveform]
V_fixture = 1.8V
V_fixture_min = 1.71V
V_fixture_max = 1.89V
R_fixture = 50Ohm
C_fixture = 0F
|   Time   V(typ)   V(min)   V(max)
0s        467.9mV    541.6mV    392.7mV
1.646ns   459.6mV    529.4mV    385.8mV
1.662ns   459.5mV    529.3mV    462.2mV
1.715ns   492.9mV    526.7mV    1.135V
1.789ns   1.113V     562.6mV    1.567V
1.886ns   1.51V      1.083V     1.792V
2.007ns   1.706V     1.451V     1.862V
2.135ns   1.764V     1.608V     1.876V
2.394ns   1.789V     1.687V     1.883V
6.5ns     1.799V     1.709V     1.889V
[Falling Waveform]
|Gnd
V_fixture = 0V
V_fixture_min = 0V
V_fixture_max = 0V
R_fixture = 50Ohm
C_fixture = 0F
|   Time   V(typ)   V(min)   V(max)
0s        1.335V     1.143V     1.517V
1.667ns   1.345V     1.164V     1.523V
1.685ns   1.345V     1.164V     1.454V
1.749ns   1.309V     1.165V     840.6mV
1.827ns   793.2mV    1.157V     402.4mV
1.923ns   384mV      764mV      121.4mV
2.056ns   100.4mV    320.6mV    23.24mV
2.184ns   32mV       105.6mV    7.601mV
2.433ns   6.857mV    17.23mV    2.371mV
6.5ns     235.1uV    428.5uV    86.1uV
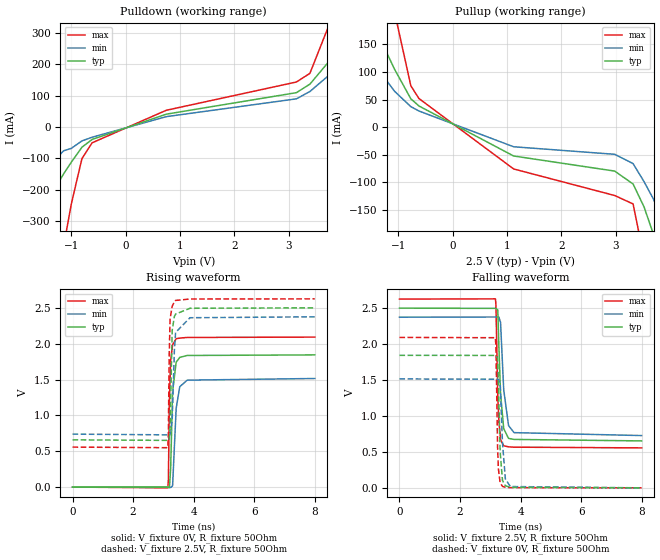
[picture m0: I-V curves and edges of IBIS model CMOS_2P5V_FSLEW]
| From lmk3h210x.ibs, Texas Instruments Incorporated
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[Model]   CMOS_2P5V_FSLEW
Model_type   Output
Polarity   Non-Inverting
Vmeas = 1.25
Vref = 1.25
Cref = 2pF
Rref = 100000
|   typ   min   max
C_comp   2.5pF   2pF   3pF
[Voltage Range]   2.5   2.375   2.625
[Temperature Range]   45   125   -40
[Pullup Reference]   2.5   2.375   2.625
[Pulldown Reference]   -0   -0   0
[Power Clamp Reference]   2.5   2.375   2.625
[GND Clamp Reference]   0   0   0
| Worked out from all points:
|   slope of the pulldown table from 0 to 0.375 V, typ, clamps not added: 17 ohm
|   slope of the pullup table from 0 to 0.375 V, typ, clamps not added: 17.9 ohm
|   falling waveform, V_fixture 2.5V, R_fixture 50Ohm: 20-80 % time 113ps typ, 151ps min, 78.6ps max; typ from 2.5 V to 0.652 V
|   rising waveform, V_fixture 0V, R_fixture 50Ohm: 20-80 % time 79.6ps typ, 110ps min, 54.9ps max; typ from 0.001 V to 1.84 V
|   rising waveform, V_fixture 2.5V, R_fixture 50Ohm: 20-80 % time 53.7ps typ, 78.4ps min, 38.6ps max; typ from 0.659 V to 2.5 V
|   falling waveform, V_fixture 0V, R_fixture 50Ohm: 20-80 % time 74.9ps typ, 92.7ps min, 56.5ps max; typ from 1.84 V to 0 V
[Pulldown]
|   Voltage   I(typ)   I(min)   I(max)
-2.5V     -596.8mA   -329.1mA   -1.849A
-2.118V   -486.9mA   -279.7mA   -1.42A
-1.54V    -267.6mA   -149.4mA   -776.3mA
-1.143V   -149.7mA   -75.83mA   -382mA
-1V       -112.2mA   -67.94mA   -245.5mA
-805mV    -64.29mA   -44.18mA   -100.8mA
-617.5mV  -39.49mA   -32.42mA   -50.2mA
747.5mV   41.23mA    33.3mA     53.68mA
3.14V     109.9mA    90.15mA    143.9mA
3.388V    137.1mA    113.6mA    171.6mA
3.717V    205.1mA    162.3mA    316mA
5V        515.4mA    382.5mA    998.6mA
[Pullup]
|   Voltage   I(typ)   I(min)   I(max)
-2.5V     424mA      288.6mA    948.6mA
-1.195V   131.5mA    81.76mA    272.2mA
-1.067V   104.9mA    64.92mA    208.7mA
-767.5mV  51.29mA    37.06mA    74.87mA
-617.5mV  38.22mA    29.12mA    51.69mA
1.123V    -52.47mA   -35.74mA   -76mA
2.982V    -79.88mA   -49.41mA   -124.2mA
3.32V     -103.3mA   -66.32mA   -139.5mA
3.522V    -145mA     -99.14mA   -237.7mA
3.688V    -192.7mA   -129.5mA   -368.8mA
4.07V     -332.4mA   -211.1mA   -768.1mA
5V        -690.7mA   -402.2mA   -1.811A
[Ramp]
R_load = 50
|   typ   min   max
dV/dt_r   1.1052/7.91176e-11   0.908564/1.09339e-10   1.25426/5.48292e-11
dV/dt_f   1.10739/1.13219e-10   0.987052/1.51381e-10   1.24097/7.84033e-11
[Falling Waveform]
V_fixture = 2.5V
V_fixture_min = 2.375V
V_fixture_max = 2.625V
R_fixture = 50Ohm
C_fixture = 0F
|   Time   V(typ)   V(min)   V(max)
0s        2.498V     2.372V     2.624V
3.173ns   2.495V     2.375V     2.627V
3.187ns   2.495V     2.375V     2.544V
3.249ns   2.472V     2.375V     1.266V
3.284ns   1.975V     2.375V     935.4mV
3.34ns    1.309V     2.3V       670.9mV
3.444ns   823.1mV    1.364V     585mV
3.604ns   687.6mV    865.6mV    570.1mV
3.786ns   673.1mV    767.5mV    565.4mV
8ns       652.4mV    726.7mV    555.4mV
[Rising Waveform]
V_fixture = 0V
V_fixture_min = 0V
V_fixture_max = 0V
R_fixture = 50Ohm
C_fixture = 0F
|   Time   V(typ)   V(min)   V(max)
0s        722uV      4.494uV    381.4uV
3.147ns   453.5uV    -649.3uV   -10.32mV
3.165ns   -2.37mV    -653.1uV   101.1mV
3.199ns   -9.604mV   -931.7uV   1.219V
3.24ns    258.2mV    -5.745mV   1.768V
3.304ns   1.33V      19.22mV    1.983V
3.422ns   1.741V     1.097V     2.069V
3.54ns    1.808V     1.399V     2.077V
3.786ns   1.835V     1.491V     2.086V
8ns       1.843V     1.514V     2.091V
[Rising Waveform]
V_fixture = 2.5V
V_fixture_min = 2.375V
V_fixture_max = 2.625V
R_fixture = 50Ohm
C_fixture = 0F
|   Time   V(typ)   V(min)   V(max)
0s        658.8mV    738.5mV    557.6mV
3.143ns   651.4mV    728.4mV    549.4mV
3.163ns   651.4mV    728.3mV    711.3mV
3.192ns   654.9mV    728.3mV    1.825V
3.221ns   831.5mV    728.2mV    2.344V
3.291ns   2.185V     946.8mV    2.522V
3.362ns   2.378V     1.896V     2.581V
3.403ns   2.412V     2.156V     2.602V
3.878ns   2.493V     2.361V     2.622V
8ns       2.499V     2.374V     2.624V
[Falling Waveform]
|Gnd
V_fixture = 0V
V_fixture_min = 0V
V_fixture_max = 0V
R_fixture = 50Ohm
C_fixture = 0F
|   Time   V(typ)   V(min)   V(max)
0s        1.842V     1.514V     2.091V
3.168ns   1.841V     1.51V      2.087V
3.186ns   1.84V      1.51V      1.977V
3.243ns   1.803V     1.51V      556mV
3.268ns   1.465V     1.51V      268.8mV
3.327ns   501.6mV    1.459V     67.87mV
3.403ns   103.8mV    628.6mV    21.15mV
3.499ns   29.04mV    122.3mV    7.466mV
3.665ns   6.794mV    18.23mV    2.566mV
8ns       168.8uV    4.494uV    66.11uV
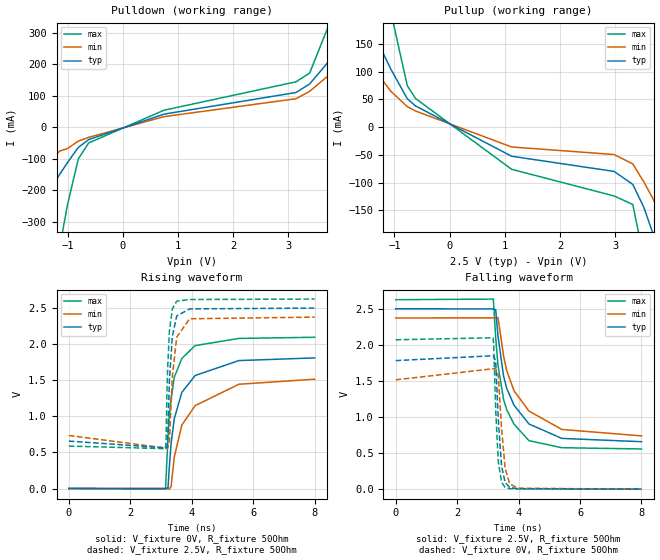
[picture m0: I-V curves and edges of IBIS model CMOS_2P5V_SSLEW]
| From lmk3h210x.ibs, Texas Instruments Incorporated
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[Model]   CMOS_2P5V_SSLEW
Model_type   Output
Polarity   Non-Inverting
Vmeas = 1.25
Vref = 1.25
Cref = 2pF
Rref = 100000
|   typ   min   max
C_comp   2.5pF   2pF   3pF
[Voltage Range]   2.5   2.375   2.625
[Temperature Range]   45   125   -40
[Pullup Reference]   2.5   2.375   2.625
[Pulldown Reference]   -0   -0   -0
[Power Clamp Reference]   2.5   2.375   2.625
[GND Clamp Reference]   0   0   0
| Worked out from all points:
|   slope of the pulldown table from 0 to 0.375 V, typ, clamps not added: 17 ohm
|   slope of the pullup table from 0 to 0.375 V, typ, clamps not added: 17.9 ohm
|   falling waveform, V_fixture 2.5V, R_fixture 50Ohm: 20-80 % time 732ps typ, 944ps min, 507ps max; typ from 2.5 V to 0.657 V
|   rising waveform, V_fixture 0V, R_fixture 50Ohm: 20-80 % time 562ps typ, 888ps min, 329ps max; typ from 0 V to 1.81 V
|   rising waveform, V_fixture 2.5V, R_fixture 50Ohm: 20-80 % time 135ps typ, 173ps min, 101ps max; typ from 0.657 V to 2.5 V
|   falling waveform, V_fixture 0V, R_fixture 50Ohm: 20-80 % time 149ps typ, 166ps min, 123ps max; typ from 1.78 V to 0 V
[Pulldown]
|   Voltage   I(typ)   I(min)   I(max)
-2.5V     -596.8mA   -329.1mA   -1.849A
-2.118V   -486.9mA   -279.7mA   -1.42A
-1.54V    -267.6mA   -149.4mA   -776.3mA
-1.143V   -149.7mA   -75.83mA   -382mA
-1V       -112.2mA   -67.94mA   -245.5mA
-805mV    -64.29mA   -44.18mA   -100.8mA
-617.5mV  -39.49mA   -32.42mA   -50.2mA
747.5mV   41.23mA    33.3mA     53.68mA
3.14V     109.9mA    90.15mA    143.9mA
3.388V    137.1mA    113.6mA    171.6mA
3.717V    205.1mA    162.3mA    316mA
5V        515.4mA    382.5mA    998.6mA
[Pullup]
|   Voltage   I(typ)   I(min)   I(max)
-2.5V     424mA      288.6mA    948.6mA
-1.195V   131.5mA    81.76mA    272.2mA
-1.067V   104.9mA    64.92mA    208.7mA
-767.5mV  51.29mA    37.06mA    74.87mA
-617.5mV  38.22mA    29.12mA    51.69mA
1.123V    -52.47mA   -35.74mA   -76mA
2.982V    -79.88mA   -49.41mA   -124.2mA
3.32V     -103.3mA   -66.32mA   -139.5mA
3.522V    -145mA     -99.14mA   -237.7mA
3.688V    -192.7mA   -129.5mA   -368.8mA
4.07V     -332.4mA   -211.1mA   -768.1mA
5V        -690.7mA   -402.2mA   -1.811A
[Ramp]
R_load = 50
|   typ   min   max
dV/dt_r   1.0856/5.6126e-10   0.908564/8.8484e-10   1.25683/3.28272e-10
dV/dt_f   1.104/7.30171e-10   0.979687/9.36773e-10   1.24004/5.05921e-10
[Falling Waveform]
V_fixture = 2.5V
V_fixture_min = 2.375V
V_fixture_max = 2.625V
R_fixture = 50Ohm
C_fixture = 0F
|   Time   V(typ)   V(min)   V(max)
0s        2.497V     2.37V      2.623V
3.178ns   2.496V     2.371V     2.632V
3.255ns   2.484V     2.371V     2.102V
3.331ns   2.116V     2.375V     1.712V
3.512ns   1.565V     1.843V     1.24V
3.613ns   1.397V     1.642V     1.1V
3.852ns   1.162V     1.362V     899.5mV
4.338ns   902.7mV    1.082V     671.4mV
5.407ns   703mV      826.8mV    574.1mV
8ns       657.2mV    737.6mV    556.6mV
[Rising Waveform]
V_fixture = 0V
V_fixture_min = 0V
V_fixture_max = 0V
R_fixture = 50Ohm
C_fixture = 0F
|   Time   V(typ)   V(min)   V(max)
0s        1.718uV    4.494uV    441.3uV
3.149ns   32.03uV    -631.1uV   -6.796mV
3.229ns   9.8mV      -4.317mV   718.7mV
3.269ns   278.4mV    -9.171mV   999.9mV
3.329ns   621.7mV    27.83mV    1.243V
3.432ns   966.9mV    432mV      1.538V
3.678ns   1.33V      878.3mV    1.801V
4.111ns   1.565V     1.148V     1.979V
5.536ns   1.772V     1.444V     2.079V
8ns       1.809V     1.514V     2.095V
[Rising Waveform]
V_fixture = 2.5V
V_fixture_min = 2.375V
V_fixture_max = 2.625V
R_fixture = 50Ohm
C_fixture = 0F
|   Time   V(typ)   V(min)   V(max)
0s        656.7mV    734.4mV    587.7mV
3.145ns   563.4mV    560.3mV    551.4mV
3.166ns   563.1mV    559.9mV    675.9mV
3.195ns   569mV      559.4mV    1.343V
3.216ns   653.1mV    559.1mV    1.652V
3.274ns   1.491V     644.8mV    2.181V
3.37ns    2.109V     1.551V     2.489V
3.512ns   2.389V     2.095V     2.595V
3.931ns   2.488V     2.351V     2.618V
8ns       2.499V     2.374V     2.624V
[Falling Waveform]
|Gnd
V_fixture = 0V
V_fixture_min = 0V
V_fixture_max = 0V
R_fixture = 50Ohm
C_fixture = 0F
|   Time   V(typ)   V(min)   V(max)
0s        1.78V      1.514V     2.068V
3.169ns   1.847V     1.667V     2.096V
3.188ns   1.847V     1.667V     2.02V
3.255ns   1.769V     1.668V     1.099V
3.341ns   958.9mV    1.573V     374.4mV
3.446ns   320.8mV    840.2mV    95.18mV
3.561ns   93.95mV    292.3mV    25.18mV
3.708ns   24.69mV    75.95mV    6.749mV
3.972ns   6.528mV    13.11mV    1.931mV
8ns       188.6uV    4.494uV    54.32uV
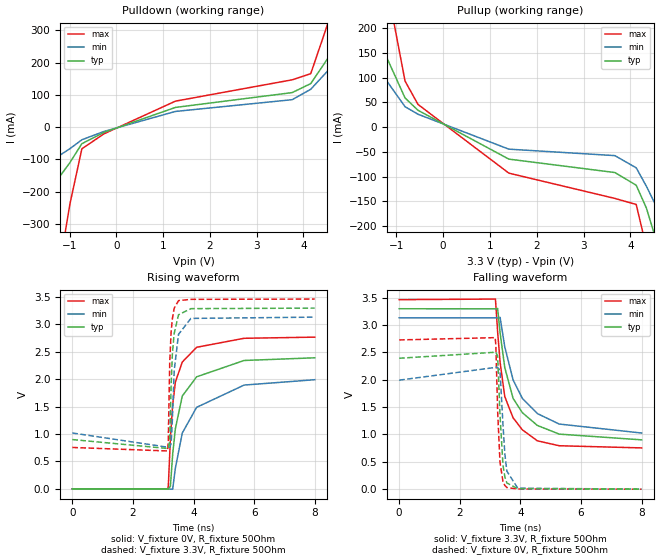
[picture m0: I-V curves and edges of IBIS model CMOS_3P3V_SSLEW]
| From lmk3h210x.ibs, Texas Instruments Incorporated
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[Model]   CMOS_3P3V_SSLEW
Model_type   Output
Polarity   Non-Inverting
Vmeas = 1.65
Vref = 1.65
Cref = 2pF
Rref = 100000
|   typ   min   max
C_comp   2.5pF   2pF   3pF
[Voltage Range]   3.3   3.135   3.465
[Temperature Range]   45   125   -40
[Pullup Reference]   3.3   3.135   3.465
[Pulldown Reference]   0   -0   -0
[Power Clamp Reference]   3.3   3.135   3.465
[GND Clamp Reference]   0   0   0
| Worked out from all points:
|   slope of the pulldown table from 0 to 0.495 V, typ, clamps not added: 17.3 ohm
|   slope of the pullup table from 0 to 0.495 V, typ, clamps not added: 17.5 ohm
|   falling waveform, V_fixture 3.3V, R_fixture 50Ohm: 20-80 % time 757ps typ, 962ps min, 525ps max; typ from 3.3 V to 0.901 V
|   rising waveform, V_fixture 0V, R_fixture 50Ohm: 20-80 % time 578ps typ, 922ps min, 333ps max; typ from 0 V to 2.39 V
|   rising waveform, V_fixture 3.3V, R_fixture 50Ohm: 20-80 % time 118ps typ, 153ps min, 89.6ps max; typ from 0.9 V to 3.3 V
|   falling waveform, V_fixture 0V, R_fixture 50Ohm: 20-80 % time 129ps typ, 147ps min, 107ps max; typ from 2.39 V to 0 V
[Pulldown]
|   Voltage   I(typ)   I(min)   I(max)
-3.3V     -900.4mA   -530.4mA   -2.688A
-2.33V    -552.8mA   -290.6mA   -1.659A
-2.31V    -545.4mA   -312mA     -1.637A
-1.221V   -155.5mA   -88.35mA   -439.6mA
-993.3mV  -110.4mA   -67mA      -239.8mA
-735.9mV  -51.28mA   -39.19mA   -67.1mA
-260.7mV  -16.04mA   -13.19mA   -20.54mA
1.264V    61.12mA    48.7mA     80.63mA
3.759V    107.1mA    85.15mA    146.8mA
4.155V    135mA      117.4mA    165.8mA
4.778V    268.6mA    215.3mA    430.8mA
6.6V      722.3mA    542mA      1.425A
[Pullup]
|   Voltage   I(typ)   I(min)   I(max)
-3.3V     622.7mA    433.5mA    1.383A
-2.023V   315.3mA    210.4mA    700.3mA
-1.736V   250.9mA    163.9mA    550.9mA
-815.1mV  59.02mA    41.28mA    93.08mA
-537.9mV  34mA       26.09mA    45.85mA
1.403V    -64.57mA   -44.46mA   -92.89mA
3.67V     -91.69mA   -57.52mA   -144mA
4.125V    -117.3mA   -82.17mA   -156.2mA
4.343V    -163.5mA   -119.4mA   -243.1mA
4.571V    -234.3mA   -163.1mA   -428mA
5.056V    -416.7mA   -272.8mA   -947.3mA
6.6V      -993.8mA   -630.3mA   -2.645A
[Ramp]
R_load = 50
|   typ   min   max
dV/dt_r   1.43531/5.78412e-10   1.19537/9.23096e-10   1.66101/3.33327e-10
dV/dt_f   1.43759/7.51834e-10   1.26307/9.57062e-10   1.62559/5.2038e-10
[Falling Waveform]
V_fixture = 3.3V
V_fixture_min = 3.135V
V_fixture_max = 3.465V
R_fixture = 50Ohm
C_fixture = 0F
|   Time   V(typ)   V(min)   V(max)
0s        3.297V     3.131V     3.463V
3.177ns   3.296V     3.131V     3.474V
3.248ns   3.304V     3.131V     2.885V
3.331ns   2.856V     3.138V     2.317V
3.485ns   2.221V     2.6V       1.691V
3.76ns    1.658V     1.995V     1.303V
4.066ns   1.397V     1.658V     1.084V
4.561ns   1.164V     1.381V     883.4mV
5.281ns   1.006V     1.19V      793.5mV
8ns       901.2mV    1.026V     753.9mV
[Rising Waveform]
V_fixture = 0V
V_fixture_min = 0V
V_fixture_max = 0V
R_fixture = 50Ohm
C_fixture = 0F
|   Time   V(typ)   V(min)   V(max)
0s        2.132uV    5.03uV     505.7uV
3.151ns   -32.73uV   -692.3uV   -5.792mV
3.17ns    -2.568mV   -696.6uV   61.77mV
3.238ns   48.33mV    -5.743mV   926.6mV
3.313ns   636.1mV    -5.073mV   1.531V
3.402ns   1.1V       381.1mV    1.95V
3.63ns    1.695V     1.02V      2.315V
4.103ns   2.045V     1.488V     2.584V
5.669ns   2.343V     1.894V     2.748V
8ns       2.392V     1.992V     2.769V
[Rising Waveform]
V_fixture = 3.3V
V_fixture_min = 3.135V
V_fixture_max = 3.465V
R_fixture = 50Ohm
C_fixture = 0F
|   Time   V(typ)   V(min)   V(max)
0s        899.8mV    1.02V      755.6mV
3.144ns   736.8mV    760.5mV    691.5mV
3.167ns   736.4mV    759.8mV    874.6mV
3.215ns   871.2mV    758.3mV    2.31V
3.262ns   1.894V     827.4mV    2.869V
3.302ns   2.463V     1.257V     3.101V
3.362ns   2.836V     2.157V     3.296V
3.505ns   3.177V     2.819V     3.435V
3.913ns   3.289V     3.111V     3.459V
8ns       3.299V     3.134V     3.464V
[Falling Waveform]
|Gnd
V_fixture = 0V
V_fixture_min = 0V
V_fixture_max = 0V
R_fixture = 50Ohm
C_fixture = 0F
|   Time   V(typ)   V(min)   V(max)
0s        2.392V     1.992V     2.727V
3.168ns   2.502V     2.224V     2.769V
3.19ns    2.503V     2.225V     2.636V
3.25ns    2.434V     2.226V     1.423V
3.326ns   1.368V     2.173V     496.5mV
3.426ns   436.2mV    1.177V     134.5mV
3.488ns   222.2mV    639.5mV    66.62mV
3.554ns   113.4mV    329.2mV    29.51mV
3.913ns   8.549mV    18.32mV    3.071mV
8ns       2.132uV    5.03uV     54.1uV
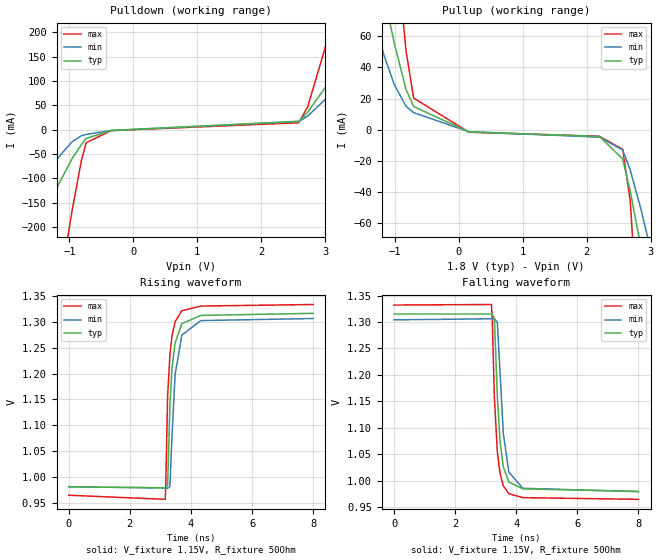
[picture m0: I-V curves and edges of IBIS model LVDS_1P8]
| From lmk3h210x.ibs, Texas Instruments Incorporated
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[Model]   LVDS_1P8
Model_type   Output
Polarity   Non-Inverting
Vmeas = 1.15
Vref = 1.15
Cref = 2pF
Rref = 100000
|   typ   min   max
C_comp   2.5pF   2pF   3pF
[Voltage Range]   1.8   1.71   1.89
[Temperature Range]   45   125   -40
[Pullup Reference]   1.8   1.71   1.89
[Pulldown Reference]   0   0   -0
[Power Clamp Reference]   1.8   1.71   1.89
[GND Clamp Reference]   0   0   0
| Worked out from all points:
|   slope of the pulldown table from 0 to 0.27 V, typ, clamps not added: 283 ohm
|   slope of the pullup table from 0 to 0.27 V, typ, clamps not added: 94.8 ohm
|   falling waveform, V_fixture 1.15V, R_fixture 50Ohm: 20-80 % time 193ps typ, 216ps min, 174ps max; typ from 1.31 V to 0.98 V
|   rising waveform, V_fixture 1.15V, R_fixture 50Ohm: 20-80 % time 188ps typ, 207ps min, 161ps max; typ from 0.982 V to 1.32 V
[Pulldown]
|   Voltage   I(typ)   I(min)   I(max)
-1.8V     -334.2mA   -177.3mA   -1.033A
-1.4V     -190.3mA   -96.45mA   -603mA
-1.19V    -117.9mA   -60.14mA   -379.3mA
-1.044V   -81.32mA   -37.26mA   -236.4mA
-952.2mV  -58.48mA   -24.35mA   -162.8mA
-811.8mV  -30.75mA   -12.39mA   -63.37mA
-736.2mV  -17.77mA   -9.591mA   -26.65mA
-347.4mV  -1.614mA   -1.508mA   -1.85mA
2.585V    17.32mA    16.98mA    14.36mA
2.725V    35.88mA    28.13mA    47.28mA
3.098V    105.4mA    74.57mA    212.8mA
3.6V      213.3mA    150mA      463.1mA
[Pullup]
|   Voltage   I(typ)   I(min)   I(max)
-1.8V     219.6mA    139.8mA    526.1mA
-1.163V   85.64mA    47.22mA    205.3mA
-1.001V   54.68mA    28.51mA    127.9mA
-822.6mV  25.89mA    15.08mA    50.77mA
-703.8mV  14.88mA    10.98mA    20.33mA
160.2mV   -1.398mA   -1.256mA   -1.595mA
2.201V    -4.308mA   -4.763mA   -4.188mA
2.563V    -18.68mA   -13.01mA   -12.53mA
2.682V    -39.38mA   -25.83mA   -45.61mA
2.849V    -75.56mA   -50.89mA   -156.7mA
3.141V    -166.2mA   -101.4mA   -430.3mA
3.6V      -333.9mA   -196.6mA   -928.3mA
[Ramp]
R_load = 50
|   typ   min   max
dV/dt_r   0.200937/1.8625e-10   0.19453/2.06021e-10   0.220219/1.59217e-10
dV/dt_f   0.201256/1.93093e-10   0.195186/2.16063e-10   0.220381/1.73421e-10
[Falling Waveform]
V_fixture = 1.15V
V_fixture_min = 1.15V
V_fixture_max = 1.15V
R_fixture = 50Ohm
C_fixture = 0F
|   Time   V(typ)   V(min)   V(max)
0s        1.315V     1.304V     1.332V
3.189ns   1.315V     1.306V     1.333V
3.215ns   1.315V     1.306V     1.305V
3.284ns   1.307V     1.306V     1.158V
3.382ns   1.159V     1.299V     1.054V
3.47ns    1.074V     1.205V     1.014V
3.578ns   1.026V     1.089V     990.2mV
3.759ns   997.4mV    1.016V     975.2mV
4.22ns    984.5mV    985.6mV    967.9mV
8ns       979.7mV    979.2mV    964.7mV
[Rising Waveform]
V_fixture = 1.15V
V_fixture_min = 1.15V
V_fixture_max = 1.15V
R_fixture = 50Ohm
C_fixture = 0F
|   Time   V(typ)   V(min)   V(max)
0s        981.5mV    982mV      965.5mV
3.157ns   979.9mV    979.4mV    957.6mV
3.174ns   979.5mV    979.4mV    978.1mV
3.237ns   985.3mV    978.8mV    1.156V
3.313ns   1.139V     982.4mV    1.237V
3.383ns   1.212V     1.083V     1.273V
3.483ns   1.259V     1.198V     1.3V
3.702ns   1.296V     1.274V     1.321V
4.327ns   1.312V     1.302V     1.33V
8ns       1.316V     1.306V     1.333V
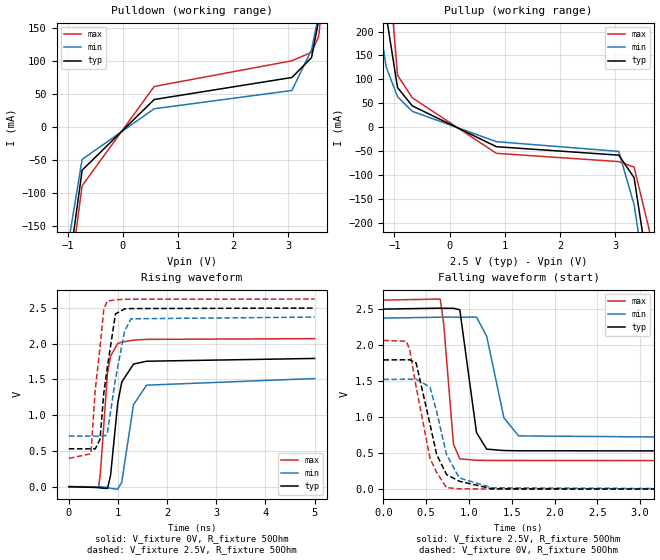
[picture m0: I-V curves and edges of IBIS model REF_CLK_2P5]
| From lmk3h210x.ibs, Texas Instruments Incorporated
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[Model]   REF_CLK_2P5
Model_type   Output
Polarity   Non-Inverting
Vmeas = 1.25
Vref = 0
Cref = 5pF
Rref = 100000
|   typ   min   max
C_comp   2.5pF   2pF   3pF
[Voltage Range]   2.5   2.375   2.625
[Temperature Range]   45   125   -40
[Pullup Reference]   2.5   2.375   2.625
[Pulldown Reference]   0   0   0
[Power Clamp Reference]   2.5   2.375   2.625
[GND Clamp Reference]   0   0   0
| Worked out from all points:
|   slope of the pulldown table from 0 to 0.375 V, typ, clamps not added: 13 ohm
|   slope of the pullup table from 0 to 0.375 V, typ, clamps not added: 17.9 ohm
|   falling waveform, V_fixture 2.5V, R_fixture 50Ohm: 20-80 % time 122ps typ, 177ps min, 88.8ps max; typ from 2.5 V to 0.53 V
|   rising waveform, V_fixture 0V, R_fixture 50Ohm: 20-80 % time 187ps typ, 216ps min, 137ps max; typ from 0 V to 1.79 V
|   rising waveform, V_fixture 2.5V, R_fixture 50Ohm: 20-80 % time 193ps typ, 222ps min, 166ps max; typ from 0.53 V to 2.5 V
|   falling waveform, V_fixture 0V, R_fixture 50Ohm: 20-80 % time 203ps typ, 203ps min, 198ps max; typ from 1.79 V to 0 V
[Pulldown]
|   Voltage   I(typ)   I(min)   I(max)
-3.3V     -2.545A    -2.251A    -2.867A
-1.221V   -401.9mA   -333.2mA   -455.9mA
-1.063V   -267.1mA   -216mA     -295.7mA
-735.9mV  -65.45mA   -49.06mA   -89.15mA
570.9mV   42.04mA    27.95mA    61.85mA
3.066V    75.52mA    55.75mA    100.9mA
3.422V    105.7mA    117.6mA    113.8mA
3.551V    162.3mA    171.4mA    137.7mA
3.64V     256.3mA    244.4mA    207.8mA
3.67V     297.1mA    276mA      248.6mA
3.729V    387.2mA    346.9mA    347mA
6.6V      6.01A      5.078A     7.197A
[Pullup]
|   Voltage   I(typ)   I(min)   I(max)
-3.3V     4.353A     3.467A     5.483A
-1.409V   654.2mA    386.8mA    941mA
-1.28V    430.8mA    228.5mA    662.7mA
-1.152V   235.8mA    126.7mA    401.9mA
-943.8mV  82.77mA    63.58mA    108.8mA
-676.5mV  44.51mA    33.13mA    61.47mA
848.1mV   -40.94mA   -30.42mA   -54.84mA
3.066V    -58.66mA   -50.79mA   -72.14mA
3.343V    -105.5mA   -161.9mA   -83.62mA
3.62V     -313.9mA   -371.7mA   -215.8mA
3.759V    -442.6mA   -489.5mA   -348.9mA
6.6V      -3.346A    -3.08A     -3.63A
[Ramp]
R_load = 50
|   typ   min   max
dV/dt_r   1.07652/1.85466e-10   0.90803/2.14345e-10   1.2424/1.36642e-10
dV/dt_f   1.18201/1.22286e-10   0.999971/1.76106e-10   1.33748/8.87369e-11
[Falling Waveform]
V_fixture = 2.5V
V_fixture_min = 2.375V
V_fixture_max = 2.625V
R_fixture = 50Ohm
C_fixture = 0F
|   Time   V(typ)   V(min)   V(max)
0s        2.5V       2.375V     2.625V
664.2ps   2.513V     2.387V     2.639V
704.5ps   2.511V     2.389V     2.298V
818.8ps   2.511V     2.388V     625.6mV
892.9ps   2.491V     2.385V     420.4mV
1.088ns   786.3mV    2.39V      401.4mV
1.207ns   555.7mV    2.123V     399.4mV
1.409ns   536.2mV    990.2mV    398mV
1.58ns    532.9mV    739.2mV    397.8mV
5ns       529.9mV    708.3mV    395.8mV
[Rising Waveform]
V_fixture = 0V
V_fixture_min = 0V
V_fixture_max = 0V
R_fixture = 50Ohm
C_fixture = 0F
|   Time   V(typ)   V(min)   V(max)
0s        782nV      2.568uV    587.1nV
606ps     -12.77mV   -352.4uV   -9.724mV
643.4ps   -18.59mV   -374.3uV   200.6mV
786.6ps   -24.99mV   -12.94mV   1.587V
849.6ps   157.4mV    -23.71mV   1.826V
994.3ps   1.165V     -35.19mV   2.003V
1.077ns   1.464V     63.68mV    2.022V
1.316ns   1.715V     1.145V     2.05V
1.58ns    1.755V     1.42V      2.061V
5ns       1.794V     1.513V     2.071V
[Rising Waveform]
V_fixture = 2.5V
V_fixture_min = 2.375V
V_fixture_max = 2.625V
R_fixture = 50Ohm
C_fixture = 0F
|   Time   V(typ)   V(min)   V(max)
0s        529.7mV    708mV      395.6mV
449.3ps   528.7mV    706.9mV    460.7mV
537.1ps   528.5mV    706.7mV    1.348V
635ps     663mV      706.4mV    1.951V
712.4ps   1.313V     706.2mV    2.482V
780.3ps   1.658V     728.6mV    2.597V
949.4ps   2.418V     1.506V     2.615V
1.135ns   2.487V     2.177V     2.621V
1.265ns   2.492V     2.349V     2.623V
5ns       2.499V     2.373V     2.625V
[Falling Waveform]
|Gnd
V_fixture = 0V
V_fixture_min = 0V
V_fixture_max = 0V
R_fixture = 50Ohm
C_fixture = 0F
|   Time   V(typ)   V(min)   V(max)
0s        1.794V     1.524V     2.065V
267.6ps   1.796V     1.525V     2.054V
307.1ps   1.796V     1.526V     1.937V
382.7ps   1.751V     1.526V     1.42V
544.2ps   906.1mV    1.418V     429.4mV
622.7ps   480.2mV    1.076V     234mV
737.5ps   204.4mV    484.3mV    21.18mV
886.6ps   110.4mV    155.9mV    5.261mV
1.272ns   4.57mV     19.23mV    2.029mV
5ns       113.7uV    155.2uV    198.6uV
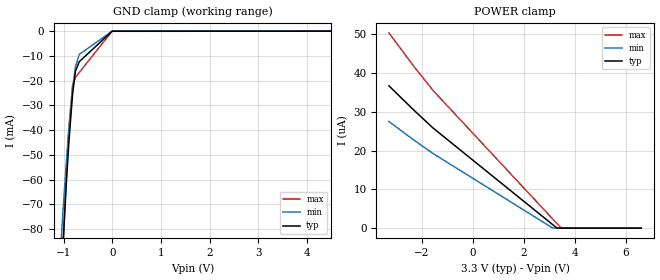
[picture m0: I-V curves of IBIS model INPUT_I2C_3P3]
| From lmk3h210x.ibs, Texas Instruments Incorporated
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[Model]   INPUT_I2C_3P3
Model_type   Input
Vinl = 0.99
Vinh = 2.31
|   typ   min   max
C_comp   0.7pF   0.5pF   0.9pF
[Voltage Range]   3.3   3.135   3.465
[Temperature Range]   45   125   -40
[Power Clamp Reference]   3.3   3.135   3.465
[GND Clamp Reference]   0   0   0
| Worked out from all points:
|   GND clamp passes 1 mA (typ) near -0.06 V on its own axis
[GND Clamp]
|   Voltage   I(typ)   I(min)   I(max)
-3.3V     -1.111A    -994.6mA   -1.235A
-1.181V   -155mA     -130.2mA   -166mA
-1.073V   -110.3mA   -92.21mA   -114.6mA
-1.063V   -106.3mA   -88.93mA   -110.1mA
-1.013V   -87.04mA   -73.2mA    -87.67mA
-943.8mV  -61.84mA   -53.24mA   -58.26mA
-894.3mV  -45.89mA   -40.53mA   -40.04mA
-815.1mV  -25.46mA   -23.28mA   -22mA
-755.7mV  -16.24mA   -14.37mA   -18.73mA
-676.5mV  -12.35mA   -9.42mA    -16.7mA
-3.3mV    -59.89uA   -42.63uA   -82.85uA
6.6V      0A         0A         0A
[POWER Clamp]
|   Voltage   I(typ)   I(min)   I(max)
-3.3V     36.74uA    27.53uA    50.4uA
-2.35V    30.64uA    22.87uA    42uA
-1.567V   25.84uA    19.26uA    35.52uA
3.125V    927.9nA    39.91nA    2.397uA
3.293V    34.8nA     0A         1.21uA
3.462V    0A         0A         23.25nA
6.6V      0A         0A         0A
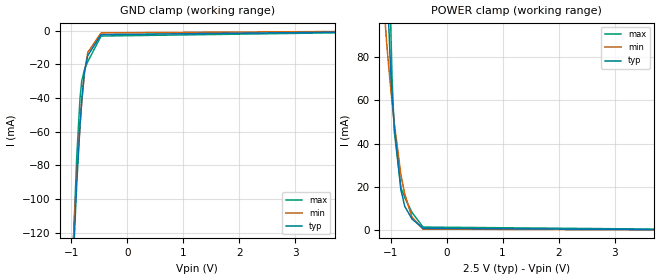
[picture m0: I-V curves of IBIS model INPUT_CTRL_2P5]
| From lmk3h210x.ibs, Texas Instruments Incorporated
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[Model]   INPUT_CTRL_2P5
Model_type   Input
Vinl = 0.65
Vinh = 1.15
|   typ   min   max
C_comp   0.7pF   0.5pF   0.9pF
[Voltage Range]   2.5   2.375   2.625
[Temperature Range]   45   125   -40
[Power Clamp Reference]   2.5   2.375   2.625
[GND Clamp Reference]   0   0   0
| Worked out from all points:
|   GND clamp passes 1 mA (typ) near -0.41 V on its own axis
|   POWER clamp passes 1 mA (typ) near -0.42 V on its own axis
[GND Clamp]
|   Voltage   I(typ)   I(min)   I(max)
-3.3V     -2.474A    -2.191A    -2.782A
-1.132V   -277.9mA   -243.6mA   -280mA
-1.043V   -198.1mA   -176.1mA   -194.8mA
-1.033V   -189.6mA   -169mA     -185.7mA
-1.013V   -173mA     -155.2mA   -167.6mA
-904.2mV  -91.28mA   -86.97mA   -75.43mA
-844.8mV  -56.1mA    -55.89mA   -39.89mA
-815.1mV  -41.69mA   -42.5mA    -30.02mA
-765.6mV  -24.25mA   -24.86mA   -23.17mA
-706.2mV  -14.74mA   -12.92mA   -18.37mA
-468.6mV  -2.382mA   -1.374mA   -3.243mA
6.6V      0A         0A         0A
[POWER Clamp]
|   Voltage   I(typ)   I(min)   I(max)
-3.3V     4.352A     3.467A     5.482A
-1.102V   157.7mA    98.45mA    260.3mA
-1.073V   126.7mA    87.91mA    205.9mA
-1.043V   101.6mA    78.59mA    156.2mA
-1.003V   76.72mA    67.34mA    101.2mA
-973.5mV  62.87mA    59.5mA     70.98mA
-933.9mV  48.26mA    49.68mA    45.87mA
-815.1mV  18.76mA    25.75mA    19.76mA
-745.8mV  11.11mA    16.79mA    15.13mA
-617.1mV  5.304mA    6.136mA    8.365mA
-419.1mV  966.3uA    632.5uA    1.565mA
6.6V      0A         0A         0A
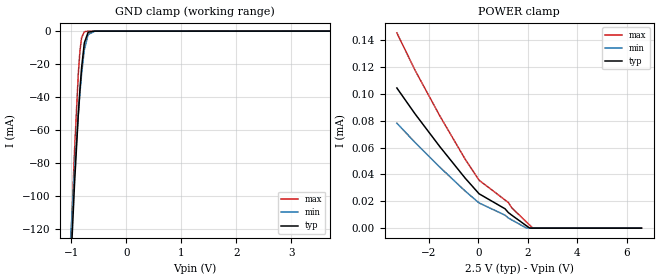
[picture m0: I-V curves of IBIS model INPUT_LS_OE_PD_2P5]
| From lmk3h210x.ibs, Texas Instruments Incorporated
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[Model]   INPUT_LS_OE_PD_2P5
Model_type   Input
Vinl = 0.65
Vinh = 1.15
|   typ   min   max
C_comp   0.7pF   0.5pF   0.9pF
[Voltage Range]   2.5   2.375   2.625
[Temperature Range]   45   125   -40
[Power Clamp Reference]   2.5   2.375   2.625
[GND Clamp Reference]   0   0   0
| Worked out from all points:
|   GND clamp passes 1 mA (typ) near -0.71 V on its own axis
[GND Clamp]
|   Voltage   I(typ)   I(min)   I(max)
-3.3V     -2.163A    -1.946A    -2.393A
-1.142V   -244.3mA   -209.2mA   -247.1mA
-1.073V   -188.3mA   -161.6mA   -183.1mA
-1.043V   -165mA     -142.2mA   -156.3mA
-943.8mV  -92.69mA   -84.35mA   -72.63mA
-874.5mV  -50.33mA   -50.21mA   -25.69mA
-844.8mV  -35.17mA   -37.37mA   -12.01mA
-815.1mV  -22.23mA   -25.95mA   -4.039mA
-765.6mV  -7.235mA   -11.31mA   -401.3uA
-696.3mV  -683.6uA   -2.04mA    -32.8uA
-577.5mV  -20.36uA   -85.13uA   -17.77uA
6.6V      0A         0A         0A
[POWER Clamp]
|   Voltage   I(typ)   I(min)   I(max)
-3.3V     104.3uA    78.12uA    145.3uA
-2.567V   85.1uA     63.83uA    117.6uA
-1.558V   60.58uA    45.32uA    83.42uA
-537.9mV  37.25uA    27.65uA    51.39uA
26.4mV    25.58uA    18.76uA    35.68uA
1.076V    14.43uA    9.676uA    20.99uA
1.214V    11.56uA    7.532uA    19.04uA
1.343V    9.745uA    6.201uA    15.26uA
1.947V    1.708uA    29.99nA    4.521uA
2.066V    127.9nA    0A         2.418uA
2.195V    0A         0A         139.3nA
6.6V      0A         0A         0A
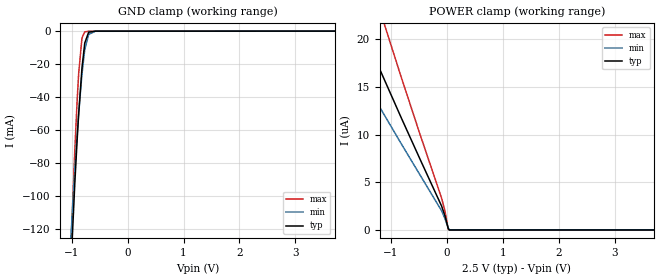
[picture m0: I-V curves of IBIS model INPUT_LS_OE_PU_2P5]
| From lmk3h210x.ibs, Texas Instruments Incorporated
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[Model]   INPUT_LS_OE_PU_2P5
Model_type   Input
Vinl = 0.65
Vinh = 1.15
|   typ   min   max
C_comp   0.7pF   0.5pF   0.9pF
[Voltage Range]   2.5   2.375   2.625
[Temperature Range]   45   125   -40
[Power Clamp Reference]   2.5   2.375   2.625
[GND Clamp Reference]   0   0   0
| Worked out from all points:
|   GND clamp passes 1 mA (typ) near -0.71 V on its own axis
[GND Clamp]
|   Voltage   I(typ)   I(min)   I(max)
-3.3V     -2.163A    -1.946A    -2.393A
-1.142V   -244.3mA   -209.2mA   -247.1mA
-1.073V   -188.3mA   -161.6mA   -183.1mA
-1.043V   -165.1mA   -142.3mA   -156.4mA
-943.8mV  -92.72mA   -84.37mA   -72.68mA
-904.2mV  -67.42mA   -64.2mA    -43.86mA
-874.5mV  -50.37mA   -50.23mA   -25.73mA
-815.1mV  -22.26mA   -25.97mA   -4.082mA
-765.6mV  -7.265mA   -11.33mA   -442.8uA
-696.3mV  -712.9uA   -2.061mA   -73.36uA
-577.5mV  -48.52uA   -105.7uA   -56.85uA
6.6V      0A         0A         0A
[POWER Clamp]
|   Voltage   I(typ)   I(min)   I(max)
-3.3V     48.12uA    36.03uA    68.71uA
-2.201V   30.77uA    23.31uA    42.91uA
-1.944V   27.08uA    20.55uA    37.61uA
-1.558V   21.72uA    16.53uA    29.96uA
-1.201V   16.89uA    12.9uA     23.15uA
-815.1mV  11.78uA    9.055uA    16.04uA
-488.4mV  7.556uA    5.871uA    10.21uA
-92.4mV   2.506uA    2.007uA    3.337uA
-33mV     1.492uA    1.198uA    2.012uA
26.4mV    145.3nA    194nA      105.6nA
46.2mV    0A         20.8nA     0A
6.6V      0A         0A         0A
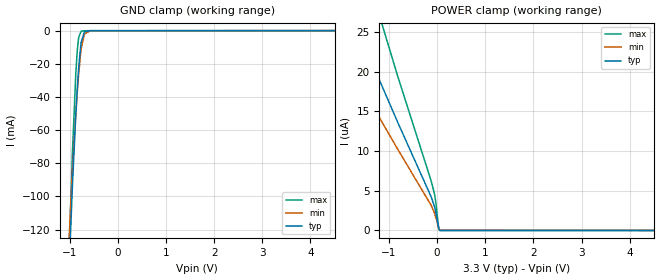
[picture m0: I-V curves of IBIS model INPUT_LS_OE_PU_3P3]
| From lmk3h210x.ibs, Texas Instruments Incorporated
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[Model]   INPUT_LS_OE_PU_3P3
Model_type   Input
Vinl = 0.65
Vinh = 1.15
|   typ   min   max
C_comp   0.7pF   0.5pF   0.9pF
[Voltage Range]   3.3   3.135   3.465
[Temperature Range]   45   125   -40
[Power Clamp Reference]   3.3   3.135   3.465
[GND Clamp Reference]   0   0   0
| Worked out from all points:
|   GND clamp passes 1 mA (typ) near -0.71 V on its own axis
[GND Clamp]
|   Voltage   I(typ)   I(min)   I(max)
-3.3V     -2.163A    -1.946A    -2.393A
-1.142V   -244.4mA   -209.2mA   -247.2mA
-1.073V   -188.4mA   -161.6mA   -183.2mA
-1.043V   -165.1mA   -142.3mA   -156.4mA
-943.8mV  -92.73mA   -84.38mA   -72.69mA
-874.5mV  -50.37mA   -50.24mA   -25.74mA
-844.8mV  -35.21mA   -37.4mA    -12.06mA
-815.1mV  -22.26mA   -25.98mA   -4.093mA
-765.6mV  -7.273mA   -11.34mA   -454.2uA
-696.3mV  -721.1uA   -2.067mA   -84.76uA
-577.5mV  -56.68uA   -111.7uA   -68.25uA
6.6V      0A         0A         0A
[POWER Clamp]
|   Voltage   I(typ)   I(min)   I(max)
-3.3V     54.26uA    40.59uA    82.77uA
-2.191V   34uA       25.29uA    49.22uA
-1.627V   25.19uA    18.85uA    36.11uA
-1.251V   19.69uA    14.77uA    28.14uA
-815.1mV  13.59uA    10.21uA    19.38uA
-122.1mV  4.225uA    3.154uA    6.217uA
-52.8mV   2.992uA    2.172uA    4.583uA
-23.1mV   2.159uA    1.57uA     3.352uA
26.4mV    496.9nA    446.9nA    636.3nA
36.3mV    217.9nA    247.1nA    219.8nA
56.1mV    0A         31.56nA    0A
6.6V      0A         0A         0A
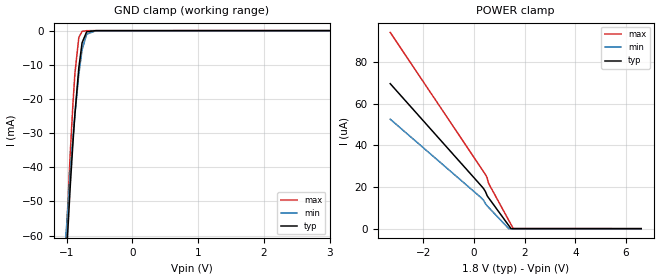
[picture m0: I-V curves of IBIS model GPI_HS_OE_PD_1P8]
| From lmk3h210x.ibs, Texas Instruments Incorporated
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[Model]   GPI_HS_OE_PD_1P8
Model_type   Input
Vinl = 0.65
Vinh = 1.15
|   typ   min   max
C_comp   0.55pF   0.44pF   0.66pF
[Voltage Range]   1.8   1.71   1.89
[Temperature Range]   45   125   -40
[Power Clamp Reference]   1.8   1.71   1.89
[GND Clamp Reference]   0   0   0
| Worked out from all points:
|   GND clamp passes 1 mA (typ) near -0.73 V on its own axis
[GND Clamp]
|   Voltage   I(typ)   I(min)   I(max)
-3.3V     -1.046A    -940.8mA   -1.157A
-1.142V   -118.3mA   -101.5mA   -119.6mA
-1.073V   -91.27mA   -78.48mA   -88.66mA
-1.043V   -80.01mA   -69.14mA   -75.72mA
-943.8mV  -45.02mA   -41.08mA   -35.24mA
-904.2mV  -32.76mA   -31.3mA    -21.3mA
-874.5mV  -24.5mA    -24.51mA   -12.52mA
-815.1mV  -10.86mA   -12.73mA   -2.013mA
-765.6mV  -3.574mA   -5.611mA   -223.9uA
-696.3mV  -364.2uA   -1.075mA   -30.26uA
-557.7mV  -16.92uA   -43.6uA    -19.9uA
6.6V      0A         0A         0A
[POWER Clamp]
|   Voltage   I(typ)   I(min)   I(max)
-3.3V     69.53uA    52.5uA     94.12uA
273.9mV   20.75uA    14.97uA    29.26uA
382.8mV   19.22uA    13.62uA    27.29uA
462mV     17.62uA    11.85uA    25.83uA
521.4mV   15.84uA    10.97uA    24.4uA
570.9mV   14.95uA    10.32uA    22.09uA
600.6mV   14.45uA    9.931uA    21.28uA
1.373V    1.524uA    19.94nA    4.039uA
1.462V    34.34nA    0A         2.055uA
1.551V    0A         0A         71.92nA
6.6V      0A         0A         0A
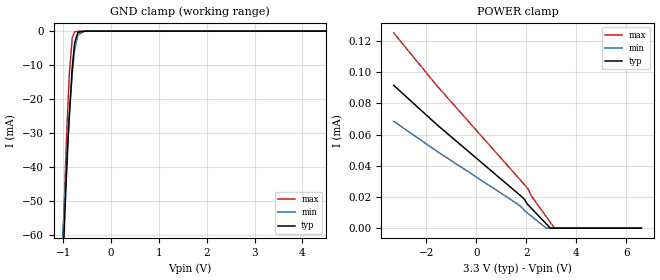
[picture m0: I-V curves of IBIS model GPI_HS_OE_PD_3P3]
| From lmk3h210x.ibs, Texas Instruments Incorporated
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[Model]   GPI_HS_OE_PD_3P3
Model_type   Input
Vinl = 0.65
Vinh = 1.15
|   typ   min   max
C_comp   0.55pF   0.44pF   0.66pF
[Voltage Range]   3.3   3.135   3.465
[Temperature Range]   45   125   -40
[Power Clamp Reference]   3.3   3.135   3.465
[GND Clamp Reference]   0   0   0
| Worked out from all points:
|   GND clamp passes 1 mA (typ) near -0.73 V on its own axis
[GND Clamp]
|   Voltage   I(typ)   I(min)   I(max)
-3.3V     -1.046A    -940.8mA   -1.157A
-1.142V   -118.3mA   -101.5mA   -119.6mA
-1.073V   -91.27mA   -78.48mA   -88.66mA
-1.043V   -80.01mA   -69.14mA   -75.72mA
-943.8mV  -45.02mA   -41.08mA   -35.24mA
-904.2mV  -32.76mA   -31.3mA    -21.3mA
-874.5mV  -24.5mA    -24.51mA   -12.52mA
-815.1mV  -10.86mA   -12.73mA   -2.013mA
-765.6mV  -3.574mA   -5.611mA   -223.9uA
-696.3mV  -364.2uA   -1.075mA   -30.26uA
-557.7mV  -16.92uA   -43.6uA    -19.9uA
6.6V      0A         0A         0A
[POWER Clamp]
|   Voltage   I(typ)   I(min)   I(max)
-3.3V     91.51uA    68.49uA    125.1uA
-1.567V   66.21uA    49.18uA    91.15uA
1.68V     22.03uA    15.17uA    32.33uA
1.848V    19.73uA    12.83uA    29.28uA
1.937V    18.26uA    11.1uA     27.67uA
2.036V    15.57uA    9.795uA    25.84uA
2.095V    14.53uA    9.03uA     24.43uA
2.185V    13.03uA    7.885uA    21.07uA
2.798V    2.768uA    12.43nA    7.364uA
2.957V    119.7nA    0A         3.838uA
3.125V    0A         0A         91.96nA
6.6V      0A         0A         0A
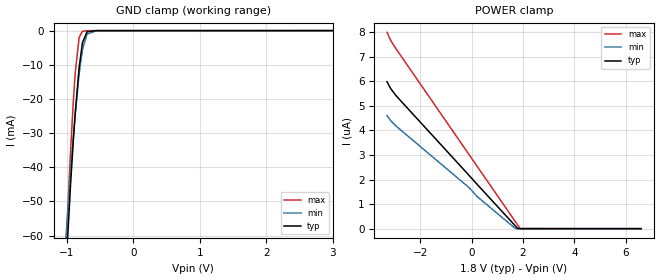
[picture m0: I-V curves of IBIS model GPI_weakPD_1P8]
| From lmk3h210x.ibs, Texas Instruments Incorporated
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[Model]   GPI_weakPD_1P8
Model_type   Input
Vinl = 0.54
Vinh = 1.26
|   typ   min   max
C_comp   0.55pF   0.44pF   0.66pF
[Voltage Range]   1.8   1.71   1.89
[Temperature Range]   45   125   -40
[Power Clamp Reference]   1.8   1.71   1.89
[GND Clamp Reference]   0   0   0
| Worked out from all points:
|   GND clamp passes 1 mA (typ) near -0.73 V on its own axis
[GND Clamp]
|   Voltage   I(typ)   I(min)   I(max)
-3.3V     -1.045A    -940.6mA   -1.157A
-1.142V   -118.3mA   -101.5mA   -119.5mA
-1.073V   -91.24mA   -78.45mA   -88.62mA
-1.043V   -79.98mA   -69.1mA    -75.68mA
-943.8mV  -44.99mA   -41.05mA   -35.22mA
-904.2mV  -32.74mA   -31.27mA   -21.28mA
-874.5mV  -24.48mA   -24.49mA   -12.51mA
-815.1mV  -10.84mA   -12.72mA   -2.002mA
-765.6mV  -3.561mA   -5.597mA   -216.9uA
-696.3mV  -357uA     -1.066mA   -24.74uA
-557.7mV  -13.06uA   -40.11uA   -14.63uA
6.6V      0A         0A         0A
[POWER Clamp]
|   Voltage   I(typ)   I(min)   I(max)
-3.3V     5.977uA    4.604uA    7.988uA
-3.161V   5.704uA    4.398uA    7.665uA
-2.954V   5.417uA    4.179uA    7.325uA
-102.3mV  2.166uA    1.668uA    3.012uA
214.5mV   1.799uA    1.304uA    2.533uA
1.7V      111.9nA    5.157nA    286.3nA
1.789V    10.2nA     0A         151.5nA
1.888V    0A         0A         1.732nA
6.6V      0A         0A         0A
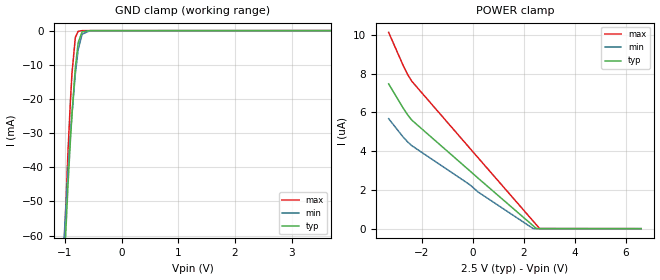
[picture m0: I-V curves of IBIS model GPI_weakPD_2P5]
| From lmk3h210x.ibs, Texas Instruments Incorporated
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[Model]   GPI_weakPD_2P5
Model_type   Input
Vinl = 0.75
Vinh = 1.75
|   typ   min   max
C_comp   0.55pF   0.44pF   0.66pF
[Voltage Range]   2.5   2.375   2.625
[Temperature Range]   45   125   -40
[Power Clamp Reference]   2.5   2.375   2.625
[GND Clamp Reference]   0   0   0
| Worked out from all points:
|   GND clamp passes 1 mA (typ) near -0.73 V on its own axis
[GND Clamp]
|   Voltage   I(typ)   I(min)   I(max)
-3.3V     -1.045A    -940.6mA   -1.157A
-1.142V   -118.3mA   -101.5mA   -119.5mA
-1.073V   -91.24mA   -78.45mA   -88.62mA
-1.043V   -79.98mA   -69.1mA    -75.68mA
-943.8mV  -44.99mA   -41.05mA   -35.22mA
-904.2mV  -32.74mA   -31.27mA   -21.28mA
-874.5mV  -24.48mA   -24.49mA   -12.51mA
-815.1mV  -10.84mA   -12.72mA   -2.002mA
-765.6mV  -3.561mA   -5.597mA   -216.9uA
-696.3mV  -357uA     -1.066mA   -24.74uA
-557.7mV  -13.06uA   -40.11uA   -14.63uA
6.6V      0A         0A         0A
[POWER Clamp]
|   Voltage   I(typ)   I(min)   I(max)
-3.3V     7.465uA    5.669uA    10.12uA
-2.736V   6.227uA    4.732uA    8.43uA
-2.548V   5.856uA    4.463uA    7.931uA
-2.389V   5.592uA    4.277uA    7.596uA
-102.3mV  2.963uA    2.252uA    4.124uA
204.6mV   2.606uA    1.893uA    3.659uA
2.363V    153.7nA    6.802nA    394.8nA
2.491V    6.927nA    0A         200.1nA
2.62V     0A         0A         5.367nA
6.6V      0A         0A         0A
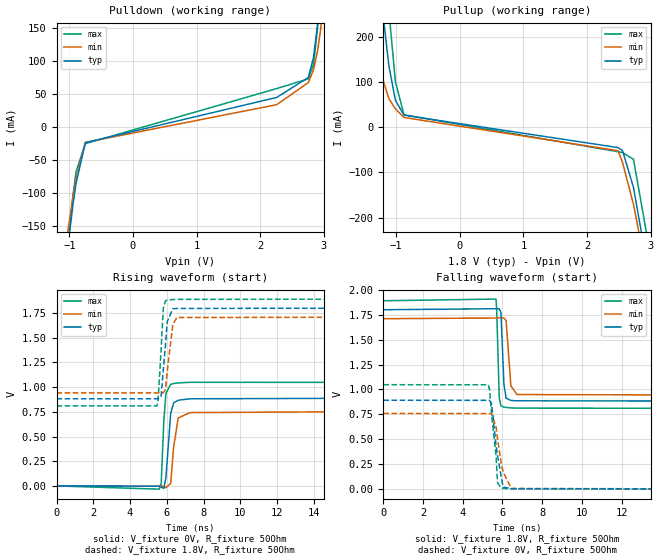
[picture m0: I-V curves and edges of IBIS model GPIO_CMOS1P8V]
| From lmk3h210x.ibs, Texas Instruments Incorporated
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[Model]   GPIO_CMOS1P8V
Model_type   Output
Polarity   Non-Inverting
Vmeas = 0.9
Vref = 0.9
Cref = 2pF
Rref = 100000
|   typ   min   max
C_comp   2.5pF   2pF   3pF
[Voltage Range]   1.8   1.71   1.89
[Temperature Range]   45   125   -40
[Pullup Reference]   1.8   1.71   1.89
[Pulldown Reference]   -0   0   -0
[Power Clamp Reference]   1.8   1.71   1.89
[GND Clamp Reference]   0   0   0
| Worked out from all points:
|   slope of the pulldown table from 0 to 0.27 V, typ, clamps not added: 47.4 ohm
|   slope of the pullup table from 0 to 0.27 V, typ, clamps not added: 49.9 ohm
|   falling waveform, V_fixture 1.8V, R_fixture 50Ohm: 20-80 % time 109ps typ, 153ps min, 80.5ps max; typ from 1.8 V to 0.881 V
|   rising waveform, V_fixture 0V, R_fixture 50Ohm: 20-80 % time 212ps typ, 238ps min, 159ps max; typ from 0 V to 0.892 V
|   rising waveform, V_fixture 1.8V, R_fixture 50Ohm: 20-80 % time 243ps typ, 280ps min, 203ps max; typ from 0.881 V to 1.8 V
|   falling waveform, V_fixture 0V, R_fixture 50Ohm: 20-80 % time 379ps typ, 371ps min, 293ps max; typ from 0.893 V to 0 V
[Pulldown]
|   Voltage   I(typ)   I(min)   I(max)
-1.8V     -871.1mA   -766.6mA   -959mA
-1.168V   -300mA     -255.7mA   -314.4mA
-941.4mV  -117.1mA   -104mA     -103.8mA
-892.8mV  -84.95mA   -78.26mA   -67.38mA
-747mV    -23.59mA   -23.03mA   -25.03mA
2.261V    44.97mA    34.04mA    58.38mA
2.758V    75.21mA    67.47mA    73.09mA
2.839V    105.8mA    87.02mA    95.54mA
2.903V    156.6mA    115.8mA    149.4mA
2.947V    204.2mA    145mA      207.8mA
2.99V     259.5mA    182mA      277.6mA
3.6V      1.263A     997.1mA    1.515A
[Pullup]
|   Voltage   I(typ)   I(min)   I(max)
-1.8V     1.242A     856.4mA    1.675A
-1.417V   579.7mA    319.7mA    856.8mA
-1.325V   430.1mA    211.1mA    666.6mA
-1.201V   243.1mA    101.8mA    418mA
-1.114V   135.6mA    63.05mA    257mA
-1.012V   59.58mA    40.42mA    101mA
-876.6mV  26.41mA    21.35mA    27.21mA
2.488V    -45.15mA   -52.07mA   -54.27mA
2.558V    -51.81mA   -77.78mA   -56.12mA
2.731V    -133.4mA   -170.8mA   -71.07mA
3.006V    -352.3mA   -370.1mA   -290.1mA
3.6V      -879.1mA   -848.4mA   -878.9mA
[Ramp]
R_load = 50
|   typ   min   max
dV/dt_r   0.535179/2.12606e-10   0.455857/2.3678e-10   0.628268/1.5909e-10
dV/dt_f   0.551258/1.0937e-10   0.4616/1.51604e-10   0.647869/8.04796e-11
[Falling Waveform]
V_fixture = 1.8V
V_fixture_min = 1.71V
V_fixture_max = 1.89V
R_fixture = 50Ohm
C_fixture = 0F
|   Time   V(typ)   V(min)   V(max)
0s        1.8V       1.71V      1.89V
5.674ns   1.81V      1.717V     1.907V
5.709ns   1.81V      1.718V     1.798V
5.839ns   1.809V     1.72V      912.2mV
5.925ns   1.77V      1.719V     836.4mV
6.074ns   1.052V     1.717V     822.8mV
6.183ns   913.3mV    1.691V     819.7mV
6.424ns   890mV      1.036V     815.3mV
6.733ns   886.3mV    949.2mV    812.7mV
25ns      881.2mV    940.6mV    810.1mV
[Rising Waveform]
V_fixture = 0V
V_fixture_min = 0V
V_fixture_max = 0V
R_fixture = 50Ohm
C_fixture = 0F
|   Time   V(typ)   V(min)   V(max)
0s        24.6uV     34.1uV     16uV
5.594ns   -1.501mV   97.35uV    -32.58mV
5.699ns   -12.34mV   98.53uV    28.77mV
5.839ns   -24.95mV   -4.882mV   655.3mV
5.955ns   85.87mV    -17.49mV   937.3mV
6.213ns   733.8mV    25.57mV    1.027V
6.374ns   839.8mV    394.3mV    1.036V
6.624ns   867.1mV    687.7mV    1.042V
7.272ns   881.2mV    741.8mV    1.048V
25ns      892mV      759.8mV    1.047V
[Rising Waveform]
V_fixture = 1.8V
V_fixture_min = 1.71V
V_fixture_max = 1.89V
R_fixture = 50Ohm
C_fixture = 0F
|   Time   V(typ)   V(min)   V(max)
0s        881.2mV    940.6mV    810.1mV
5.467ns   881.1mV    940.8mV    809.5mV
5.525ns   881.1mV    940.8mV    867mV
5.688ns   900.5mV    940.8mV    1.362V
5.81ns    1.171V     940.8mV    1.794V
5.928ns   1.424V     974.5mV    1.873V
6.023ns   1.66V      1.155V     1.879V
6.329ns   1.792V     1.634V     1.885V
6.552ns   1.795V     1.703V     1.887V
25ns      1.8V       1.71V      1.89V
[Falling Waveform]
|Gnd
V_fixture = 0V
V_fixture_min = 0V
V_fixture_max = 0V
R_fixture = 50Ohm
C_fixture = 0F
|   Time   V(typ)   V(min)   V(max)
0s        892.5mV    759.8mV    1.048V
5.287ns   890.8mV    758.2mV    1.047V
5.352ns   890.8mV    758.2mV    994.2mV
5.452ns   857.7mV    758.2mV    743mV
5.682ns   435.3mV    619.9mV    321.6mV
5.751ns   339.1mV    506.7mV    64.81mV
5.935ns   128.7mV    265.9mV    10.9mV
6.036ns   20.56mV    171.7mV    8.436mV
6.45ns    5.023mV    6.483mV    2.667mV
25ns      13.85uV    20.17uV    7.44uV
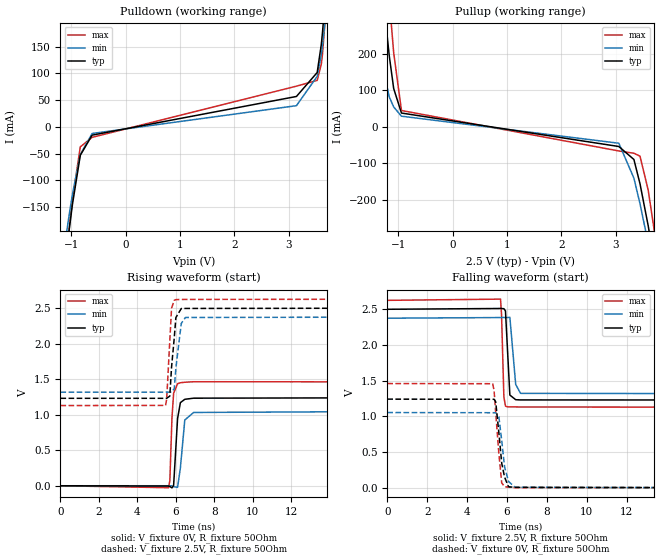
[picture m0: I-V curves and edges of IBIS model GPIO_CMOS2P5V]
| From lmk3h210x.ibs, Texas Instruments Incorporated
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[Model]   GPIO_CMOS2P5V
Model_type   Output
Polarity   Non-Inverting
Vmeas = 1.25
Vref = 1.25
Cref = 2pF
Rref = 100000
|   typ   min   max
C_comp   2.5pF   2pF   3pF
[Voltage Range]   2.5   2.375   2.625
[Temperature Range]   45   125   -40
[Pullup Reference]   2.5   2.375   2.625
[Pulldown Reference]   0   0   0
[Power Clamp Reference]   2.5   2.375   2.625
[GND Clamp Reference]   0   0   0
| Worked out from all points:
|   slope of the pulldown table from 0 to 0.375 V, typ, clamps not added: 47.4 ohm
|   slope of the pullup table from 0 to 0.375 V, typ, clamps not added: 49.2 ohm
|   falling waveform, V_fixture 2.5V, R_fixture 50Ohm: 20-80 % time 115ps typ, 160ps min, 85.6ps max; typ from 2.5 V to 1.23 V
|   rising waveform, V_fixture 0V, R_fixture 50Ohm: 20-80 % time 156ps typ, 183ps min, 122ps max; typ from 0 V to 1.24 V
|   rising waveform, V_fixture 2.5V, R_fixture 50Ohm: 20-80 % time 218ps typ, 251ps min, 187ps max; typ from 1.23 V to 2.5 V
|   falling waveform, V_fixture 0V, R_fixture 50Ohm: 20-80 % time 265ps typ, 266ps min, 268ps max; typ from 1.24 V to 0 V
[Pulldown]
|   Voltage   I(typ)   I(min)   I(max)
-2.5V     -1.524A    -1.357A    -1.689A
-1.097V   -239.7mA   -203.9mA   -245.5mA
-1.03V    -184.2mA   -157.7mA   -181.7mA
-977.5mV  -143.4mA   -124.9mA   -134.3mA
-835mV    -53.01mA   -51.34mA   -37.25mA
-617.5mV  -15.31mA   -12.22mA   -19.45mA
3.14V     56.88mA    39.7mA     76.16mA
3.522V    101.7mA    94.46mA    86.9mA
3.598V    154.4mA    135.1mA    117.6mA
3.62V     177.1mA    152.1mA    136.6mA
3.695V    269.1mA    222.8mA    234.3mA
5V        2.512A     2.121A     2.95A
[Pullup]
|   Voltage   I(typ)   I(min)   I(max)
-2.5V     2.504A     1.923A     3.207A
-1.458V   648.4mA    372.5mA    943.2mA
-1.345V   462.8mA    233.8mA    708.8mA
-1.262V   333.6mA    149.2mA    540.8mA
-1.165V   195.7mA    82.5mA     350.4mA
-1.083V   105.3mA    54.74mA    203.3mA
-940mV    38.1mA     29.47mA    45.1mA
3.058V    -53.7mA    -44.73mA   -65.91mA
3.335V    -89.24mA   -140.5mA   -72.19mA
3.447V    -155.7mA   -210.6mA   -80.12mA
3.598V    -271.2mA   -318.9mA   -173.3mA
5V        -1.529A    -1.469A    -1.566A
[Ramp]
R_load = 50
|   typ   min   max
dV/dt_r   0.744667/1.56077e-10   0.632096/1.80709e-10   0.875756/1.21384e-10
dV/dt_f   0.762305/1.14339e-10   0.635167/1.59687e-10   0.897768/8.53322e-11
[Falling Waveform]
V_fixture = 2.5V
V_fixture_min = 2.375V
V_fixture_max = 2.625V
R_fixture = 50Ohm
C_fixture = 0F
|   Time   V(typ)   V(min)   V(max)
0s        2.5V       2.375V     2.625V
5.675ns   2.511V     2.384V     2.642V
5.725ns   2.51V      2.386V     2.422V
5.842ns   2.508V     2.385V     1.273V
5.922ns   2.477V     2.384V     1.145V
6ns       2.058V     2.383V     1.135V
6.142ns   1.299V     2.388V     1.134V
6.434ns   1.234V     1.448V     1.133V
6.677ns   1.231V     1.323V     1.132V
25ns      1.229V     1.316V     1.128V
[Rising Waveform]
V_fixture = 0V
V_fixture_min = 0V
V_fixture_max = 0V
R_fixture = 50Ohm
C_fixture = 0F
|   Time   V(typ)   V(min)   V(max)
0s        30.87uV    41.29uV    21.41uV
5.619ns   -4.088mV   130.8uV    -27.64mV
5.688ns   -11.15mV   131.9uV    71.91mV
5.798ns   -29.58mV   -2.741mV   952.7mV
5.884ns   4.456mV    -13.21mV   1.301V
6.089ns   943.7mV    -22.5mV    1.435V
6.235ns   1.169V     248.8mV    1.449V
6.465ns   1.216V     925.2mV    1.456V
6.926ns   1.232V     1.031V     1.463V
25ns      1.241V     1.054V     1.46V
[Rising Waveform]
V_fixture = 2.5V
V_fixture_min = 2.375V
V_fixture_max = 2.625V
R_fixture = 50Ohm
C_fixture = 0F
|   Time   V(typ)   V(min)   V(max)
0s        1.23V      1.316V     1.128V
5.466ns   1.23V      1.317V     1.13V
5.523ns   1.23V      1.317V     1.219V
5.685ns   1.261V     1.317V     2.036V
5.777ns   1.67V      1.317V     2.498V
5.916ns   2.075V     1.363V     2.608V
6ns       2.365V     1.654V     2.618V
6.283ns   2.493V     2.284V     2.62V
6.501ns   2.494V     2.367V     2.621V
25ns      2.5V       2.375V     2.625V
[Falling Waveform]
|Gnd
V_fixture = 0V
V_fixture_min = 0V
V_fixture_max = 0V
R_fixture = 50Ohm
C_fixture = 0F
|   Time   V(typ)   V(min)   V(max)
0s        1.242V     1.054V     1.46V
5.284ns   1.24V      1.052V     1.458V
5.353ns   1.24V      1.052V     1.355V
5.433ns   1.204V     1.052V     1.051V
5.59ns    774.3mV    996.5mV    482mV
5.734ns   344.1mV    662.6mV    69.88mV
5.877ns   150.4mV    292.5mV    15.38mV
6.075ns   15.3mV     88.91mV    10.21mV
6.407ns   6.42mV     8.191mV    3.516mV
25ns      17.46uV    24.9uV     10.71uV
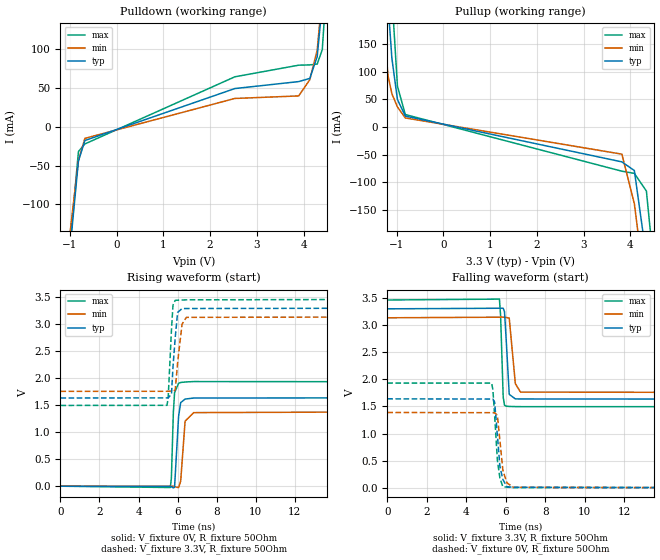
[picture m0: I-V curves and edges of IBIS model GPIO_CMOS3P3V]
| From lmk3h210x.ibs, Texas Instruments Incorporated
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[Model]   GPIO_CMOS3P3V
Model_type   Output
Polarity   Non-Inverting
Vmeas = 1.65
Vref = 1.65
Cref = 2pF
Rref = 100000
|   typ   min   max
C_comp   2.5pF   2pF   3pF
[Voltage Range]   3.3   3.135   3.465
[Temperature Range]   45   125   -40
[Pullup Reference]   3.3   3.135   3.465
[Pulldown Reference]   0   0   0
[Power Clamp Reference]   3.3   3.135   3.465
[GND Clamp Reference]   0   0   0
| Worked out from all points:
|   slope of the pulldown table from 0 to 0.495 V, typ, clamps not added: 47.6 ohm
|   slope of the pullup table from 0 to 0.495 V, typ, clamps not added: 48.6 ohm
|   falling waveform, V_fixture 3.3V, R_fixture 50Ohm: 20-80 % time 128ps typ, 182ps min, 95.5ps max; typ from 3.3 V to 1.63 V
|   rising waveform, V_fixture 0V, R_fixture 50Ohm: 20-80 % time 127ps typ, 150ps min, 101ps max; typ from 0 V to 1.64 V
|   rising waveform, V_fixture 3.3V, R_fixture 50Ohm: 20-80 % time 191ps typ, 221ps min, 168ps max; typ from 1.63 V to 3.3 V
|   falling waveform, V_fixture 0V, R_fixture 50Ohm: 20-80 % time 220ps typ, 223ps min, 214ps max; typ from 1.64 V to 0 V
[Pulldown]
|   Voltage   I(typ)   I(min)   I(max)
-3.3V     -2.268A    -2.039A    -2.516A
-1.043V   -194.5mA   -166.2mA   -193.6mA
-1.003V   -163mA     -140.6mA   -157.2mA
-815.1mV  -43.94mA   -43.3mA    -31.74mA
-676.5mV  -17.5mA    -14.71mA   -21.91mA
2.531V    49.51mA    36.74mA    64.66mA
3.897V    58.49mA    40mA       79.66mA
4.135V    62.57mA    60.95mA    80.04mA
4.293V    90.76mA    99.04mA    81.08mA
4.402V    159.4mA    171.2mA    99.81mA
4.511V    291.7mA    286mA      200mA
6.6V      3.98A      3.446A     4.626A
[Pullup]
|   Voltage   I(typ)   I(min)   I(max)
-3.3V     3.976A     3.179A     4.987A
-1.409V   567.9mA    310.8mA    843.4mA
-1.33V    438.9mA    217.1mA    679.2mA
-1.181V   217.5mA    90.96mA    382.8mA
-1.102V   123.9mA    59.97mA    237.6mA
-983.4mV  49.67mA    36.12mA    73.66mA
-815.1mV  19.6mA     16.27mA    22.45mA
3.818V    -63.24mA   -49.27mA   -80.13mA
4.085V    -78.96mA   -139mA     -84.06mA
4.343V    -235.7mA   -311.6mA   -116.1mA
4.65V     -495.2mA   -551.4mA   -381.3mA
6.6V      -2.282A    -2.188A    -2.364A
[Ramp]
R_load = 50
|   typ   min   max
dV/dt_r   0.983283/1.26989e-10   0.83146/1.4981e-10   1.15909/1.00096e-10
dV/dt_f   1.00018/1.27789e-10   0.827205/1.81519e-10   1.18074/9.55036e-11
[Falling Waveform]
V_fixture = 3.3V
V_fixture_min = 3.135V
V_fixture_max = 3.465V
R_fixture = 50Ohm
C_fixture = 0F
|   Time   V(typ)   V(min)   V(max)
0s        3.3V       3.135V     3.463V
5.675ns   3.311V     3.146V     3.479V
5.735ns   3.31V      3.148V     3.165V
5.865ns   3.311V     3.146V     1.674V
5.931ns   3.248V     3.144V     1.524V
6.015ns   2.743V     3.142V     1.506V
6.171ns   1.724V     3.129V     1.501V
6.48ns    1.64V      1.92V      1.498V
6.743ns   1.639V     1.765V     1.497V
25ns      1.633V     1.756V     1.495V
[Rising Waveform]
V_fixture = 0V
V_fixture_min = 0V
V_fixture_max = 0V
R_fixture = 50Ohm
C_fixture = 0F
|   Time   V(typ)   V(min)   V(max)
0s        34.78uV    45.03uV    25.68uV
5.631ns   -5.469mV   133.1uV    -24.38mV
5.686ns   -11.04mV   134uV      155.2mV
5.786ns   -30.8mV    -1.248mV   1.363V
5.848ns   -18.65mV   -8.768mV   1.73V
6.055ns   1.294V     -26.51mV   1.906V
6.162ns   1.547V     94.54mV    1.92V
6.388ns   1.613V     1.204V     1.929V
6.827ns   1.632V     1.362V     1.937V
25ns      1.639V     1.386V     1.932V
[Rising Waveform]
V_fixture = 3.3V
V_fixture_min = 3.135V
V_fixture_max = 3.465V
R_fixture = 50Ohm
C_fixture = 0F
|   Time   V(typ)   V(min)   V(max)
0s        1.633V     1.756V     1.495V
5.46ns    1.635V     1.757V     1.497V
5.52ns    1.635V     1.758V     1.631V
5.691ns   1.705V     1.758V     2.906V
5.769ns   2.215V     1.758V     3.355V
5.883ns   2.757V     1.783V     3.441V
6.004ns   3.216V     2.287V     3.443V
6.231ns   3.288V     2.998V     3.446V
6.454ns   3.289V     3.126V     3.45V
25ns      3.3V       3.135V     3.463V
[Falling Waveform]
|Gnd
V_fixture = 0V
V_fixture_min = 0V
V_fixture_max = 0V
R_fixture = 50Ohm
C_fixture = 0F
|   Time   V(typ)   V(min)   V(max)
0s        1.641V     1.389V     1.932V
5.28ns    1.637V     1.386V     1.931V
5.343ns   1.637V     1.386V     1.811V
5.432ns   1.581V     1.386V     1.335V
5.57ns    972.2mV    1.337V     512mV
5.699ns   394.9mV    871.5mV    180.3mV
5.848ns   155mV      323.8mV    20.02mV
6.051ns   20.01mV    92.76mV    13.43mV
6.388ns   11.01mV    10.23mV    4.824mV
25ns      19.08uV    26.23uV    12.37uV
